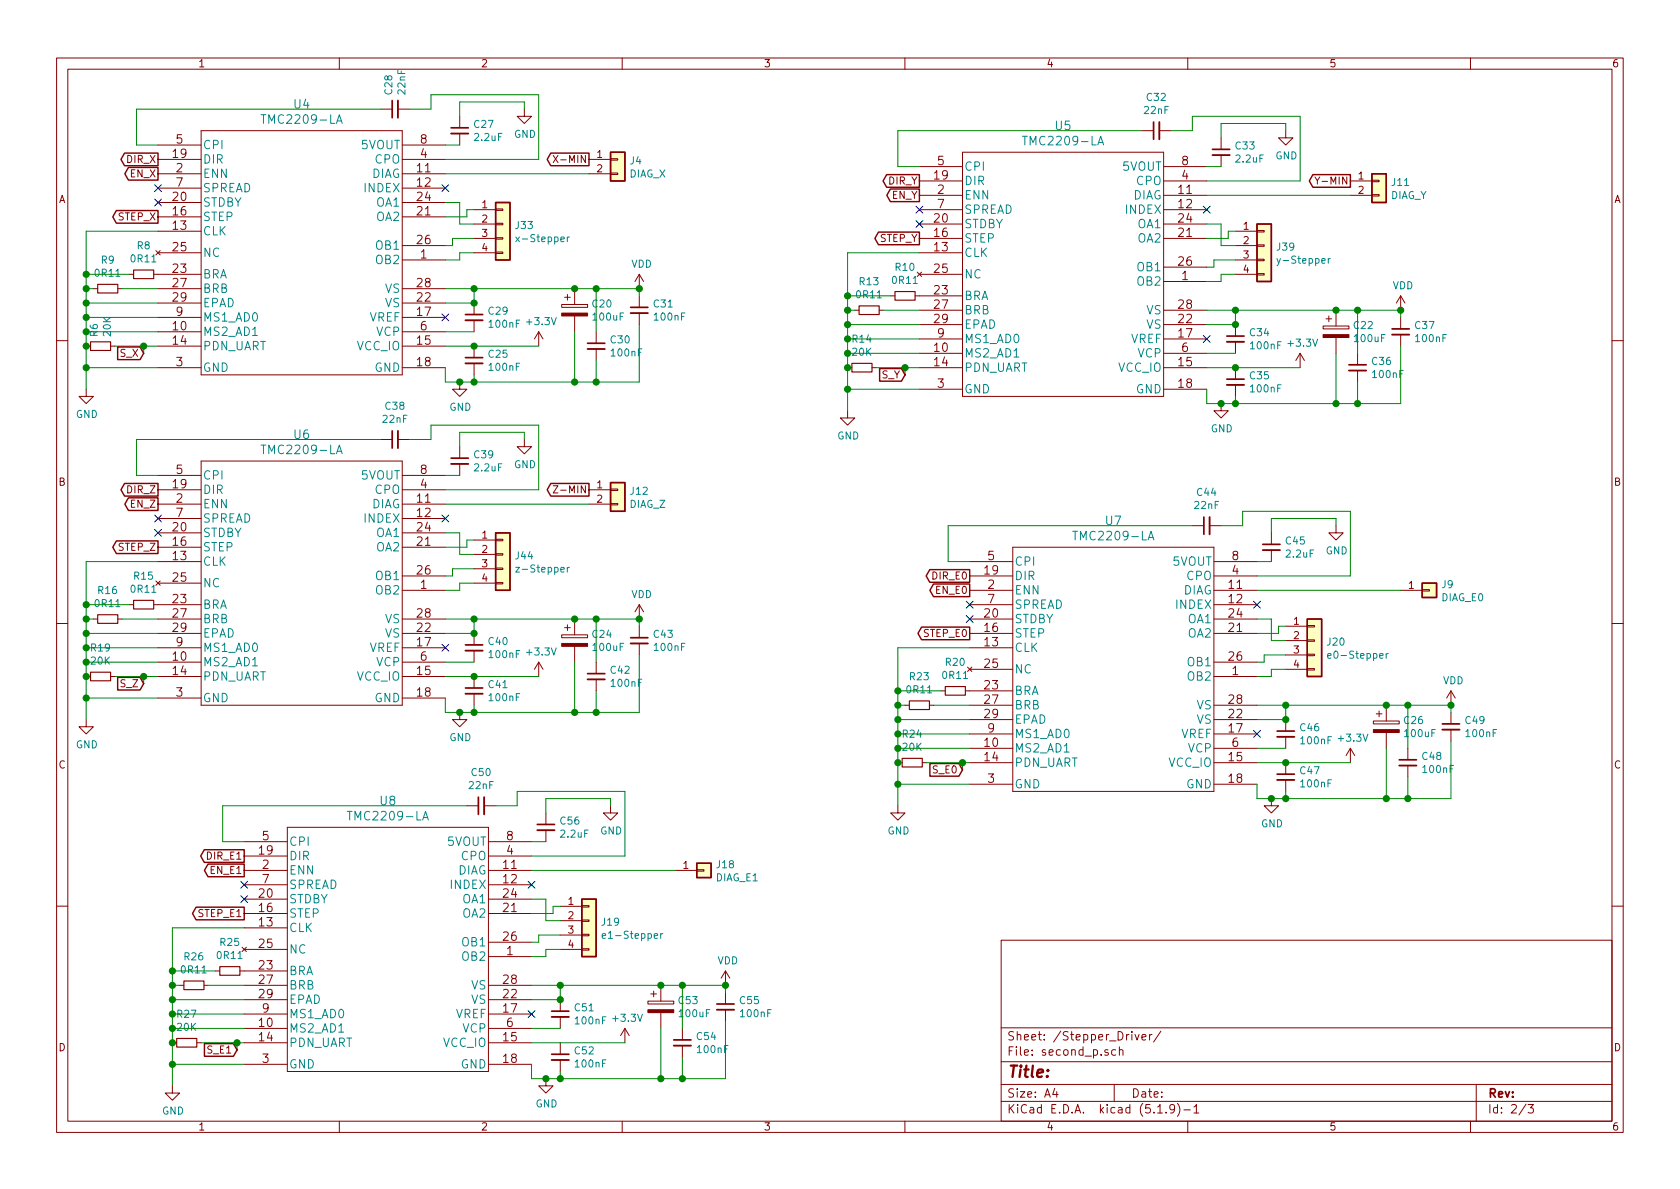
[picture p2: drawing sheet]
<svg xmlns="http://www.w3.org/2000/svg" width="297mm" height="210mm" viewBox="0 0 297 210" stroke-linecap="round" stroke-linejoin="round" font-family="sans-serif">
<defs><g id="words">
<text font-size="2.8" fill="#840000" x="178" y="190.5">Title:</text>
<g font-size="2.1" fill="#008484">
<text x="46.9" y="21.9">TMC2209-LA</text>
<text x="52" y="19.2">U4</text>
<text x="186.6" y="23">U5</text>
<text x="35.8" y="28.9">DIR</text>
<text x="35.8" y="26.4">CPI</text>
<text x="63.9" y="26.4">5VOUT</text>
<text x="66.3" y="28.9">CPO</text>
<text x="181.5" y="25.7">TMC2209-LA</text>
<text x="35.8" y="31.5">ENN</text>
<text x="35.8" y="34">SPREAD</text>
<text x="64.5" y="34">INDEX</text>
<text x="65.7" y="31.5">DIAG</text>
<text x="170.4" y="32.7">DIR</text>
<text x="170.4" y="35.3">ENN</text>
<text x="170.4" y="30.2">CPI</text>
<text x="198.5" y="30.2">5VOUT</text>
<text x="200.3" y="35.3">DIAG</text>
<text x="201" y="32.7">CPO</text>
<text x="35.8" y="41.6">CLK</text>
<text x="35.8" y="39.1">STEP</text>
<text x="35.8" y="36.5">STDBY</text>
<text x="66.6" y="39.1">OA2</text>
<text x="66.6" y="36.5">OA1</text>
<text x="170.4" y="40.4">STDBY</text>
<text x="170.4" y="37.8">SPREAD</text>
<text x="199.1" y="37.8">INDEX</text>
<text x="201.2" y="40.4">OA1</text>
<text x="35.8" y="45.4">NC</text>
<text x="66.6" y="46.7">OB2</text>
<text x="66.6" y="44.2">OB1</text>
<text x="170.4" y="45.4">CLK</text>
<text x="170.4" y="42.9">STEP</text>
<text x="201.2" y="42.9">OA2</text>
<text x="201.2" y="48">OB1</text>
<text x="35.8" y="49.2">BRA</text>
<text x="35.8" y="51.8">BRB</text>
<text x="68.1" y="51.8">VS</text>
<text x="170.4" y="53.1">BRA</text>
<text x="170.4" y="49.2">NC</text>
<text x="201.2" y="50.5">OB2</text>
<text x="35.8" y="59.4">MS2_AD1</text>
<text x="35.8" y="54.3">EPAD</text>
<text x="35.8" y="56.9">MS1_AD0</text>
<text x="65.3" y="56.9">VREF</text>
<text x="66.6" y="59.4">VCP</text>
<text x="68.1" y="54.3">VS</text>
<text x="170.4" y="55.6">BRB</text>
<text x="170.4" y="58.1">EPAD</text>
<text x="202.7" y="58.1">VS</text>
<text x="202.7" y="55.6">VS</text>
<text x="35.8" y="61.9">PDN_UART</text>
<text x="35.8" y="65.8">GND</text>
<text x="63.1" y="61.9">VCC_IO</text>
<text x="66.2" y="65.8">GND</text>
<text x="170.4" y="63.2">MS2_AD1</text>
<text x="170.4" y="65.8">PDN_UART</text>
<text x="170.4" y="60.7">MS1_AD0</text>
<text x="197.7" y="65.8">VCC_IO</text>
<text x="199.9" y="60.7">VREF</text>
<text x="201.2" y="63.2">VCP</text>
<text x="170.4" y="69.6">GND</text>
<text x="200.8" y="69.6">GND</text>
<text x="52" y="77.6">U6</text>
<text x="46.9" y="80.3">TMC2209-LA</text>
<text x="35.8" y="87.3">DIR</text>
<text x="35.8" y="89.9">ENN</text>
<text x="35.8" y="84.8">CPI</text>
<text x="63.9" y="84.8">5VOUT</text>
<text x="65.7" y="89.9">DIAG</text>
<text x="66.3" y="87.3">CPO</text>
<text x="35.8" y="95">STDBY</text>
<text x="35.8" y="92.4">SPREAD</text>
<text x="64.5" y="92.4">INDEX</text>
<text x="66.6" y="95">OA1</text>
<text x="190.4" y="95.5">TMC2209-LA</text>
<text x="195.5" y="92.9">U7</text>
<text x="35.8" y="100">CLK</text>
<text x="35.8" y="97.5">STEP</text>
<text x="66.6" y="97.5">OA2</text>
<text x="179.3" y="100">CPI</text>
<text x="207.4" y="100">5VOUT</text>
<text x="35.8" y="107.7">BRA</text>
<text x="35.8" y="103.9">NC</text>
<text x="66.6" y="105.1">OB2</text>
<text x="66.6" y="102.6">OB1</text>
<text x="179.3" y="102.6">DIR</text>
<text x="179.3" y="105.1">ENN</text>
<text x="179.3" y="107.7">SPREAD</text>
<text x="208" y="107.7">INDEX</text>
<text x="209.2" y="105.1">DIAG</text>
<text x="209.9" y="102.6">CPO</text>
<text x="35.8" y="110.2">BRB</text>
<text x="35.8" y="112.7">EPAD</text>
<text x="68.1" y="112.7">VS</text>
<text x="68.1" y="110.2">VS</text>
<text x="179.3" y="112.7">STEP</text>
<text x="179.3" y="110.2">STDBY</text>
<text x="210.1" y="112.7">OA2</text>
<text x="210.1" y="110.2">OA1</text>
<text x="35.8" y="117.8">MS2_AD1</text>
<text x="35.8" y="115.3">MS1_AD0</text>
<text x="65.3" y="115.3">VREF</text>
<text x="66.6" y="117.8">VCP</text>
<text x="179.3" y="115.3">CLK</text>
<text x="179.3" y="119.1">NC</text>
<text x="210.1" y="117.8">OB1</text>
<text x="35.8" y="120.4">PDN_UART</text>
<text x="35.8" y="124.2">GND</text>
<text x="63.1" y="120.4">VCC_IO</text>
<text x="66.2" y="124.2">GND</text>
<text x="179.3" y="122.9">BRA</text>
<text x="179.3" y="125.4">BRB</text>
<text x="210.1" y="120.4">OB2</text>
<text x="211.6" y="125.4">VS</text>
<text x="179.3" y="128">EPAD</text>
<text x="179.3" y="130.5">MS1_AD0</text>
<text x="208.8" y="130.5">VREF</text>
<text x="211.6" y="128">VS</text>
<text x="179.3" y="133.1">MS2_AD1</text>
<text x="179.3" y="135.6">PDN_UART</text>
<text x="206.6" y="135.6">VCC_IO</text>
<text x="210.1" y="133.1">VCP</text>
<text x="67.2" y="142.4">U8</text>
<text x="179.3" y="139.4">GND</text>
<text x="209.7" y="139.4">GND</text>
<text x="51.1" y="149.6">CPI</text>
<text x="62.2" y="145.1">TMC2209-LA</text>
<text x="79.1" y="149.6">5VOUT</text>
<text x="51.1" y="152.1">DIR</text>
<text x="51.1" y="154.7">ENN</text>
<text x="80.9" y="154.7">DIAG</text>
<text x="81.6" y="152.1">CPO</text>
<text x="51.1" y="159.7">STDBY</text>
<text x="51.1" y="157.2">SPREAD</text>
<text x="79.7" y="157.2">INDEX</text>
<text x="81.8" y="159.7">OA1</text>
<text x="51.1" y="164.8">CLK</text>
<text x="51.1" y="162.3">STEP</text>
<text x="81.8" y="162.3">OA2</text>
<text x="81.8" y="167.4">OB1</text>
<text x="51.1" y="172.4">BRA</text>
<text x="51.1" y="168.6">NC</text>
<text x="81.8" y="169.9">OB2</text>
<text x="51.1" y="175">BRB</text>
<text x="51.1" y="177.5">EPAD</text>
<text x="83.3" y="177.5">VS</text>
<text x="83.3" y="175">VS</text>
<text x="51.1" y="182.6">MS2_AD1</text>
<text x="51.1" y="185.1">PDN_UART</text>
<text x="51.1" y="180.1">MS1_AD0</text>
<text x="78.3" y="185.1">VCC_IO</text>
<text x="80.5" y="180.1">VREF</text>
<text x="81.8" y="182.6">VCP</text>
<text x="51.1" y="188.9">GND</text>
<text x="81.5" y="188.9">GND</text>
</g>
<g font-size="2.1" fill="#840000">
<text x="30.6" y="27.9">19</text>
<text x="31.2" y="25.4">5</text>
<text x="74.3" y="27.9">4</text>
<text x="74.3" y="25.4">8</text>
<text x="165.8" y="29.2">5</text>
<text x="209" y="29.2">8</text>
<text x="30.6" y="35.6">20</text>
<text x="31.2" y="30.5">2</text>
<text x="31.2" y="33">7</text>
<text x="73.8" y="30.5">11</text>
<text x="73.8" y="33">12</text>
<text x="73.8" y="35.6">24</text>
<text x="165.2" y="31.7">19</text>
<text x="165.8" y="34.3">2</text>
<text x="208.4" y="34.3">11</text>
<text x="209" y="31.7">4</text>
<text x="30.6" y="40.6">13</text>
<text x="30.6" y="38.1">16</text>
<text x="73.8" y="38.1">21</text>
<text x="165.2" y="41.9">16</text>
<text x="165.2" y="39.4">20</text>
<text x="165.8" y="36.8">7</text>
<text x="208.4" y="36.8">12</text>
<text x="208.4" y="41.9">21</text>
<text x="208.4" y="39.4">24</text>
<text x="30.6" y="44.4">25</text>
<text x="73.8" y="43.2">26</text>
<text x="74.3" y="45.7">1</text>
<text x="165.2" y="44.4">13</text>
<text x="208.4" y="47">26</text>
<text x="30.6" y="48.3">23</text>
<text x="30.6" y="50.8">27</text>
<text x="30.6" y="53.3">29</text>
<text x="73.8" y="53.3">22</text>
<text x="73.8" y="50.8">28</text>
<text x="165.2" y="52.1">23</text>
<text x="165.2" y="48.3">25</text>
<text x="209" y="49.5">1</text>
<text x="30.6" y="58.4">10</text>
<text x="31.2" y="55.9">9</text>
<text x="73.8" y="55.9">17</text>
<text x="74.3" y="58.4">6</text>
<text x="165.2" y="54.6">27</text>
<text x="165.2" y="57.1">29</text>
<text x="165.8" y="59.7">9</text>
<text x="208.4" y="59.7">17</text>
<text x="208.4" y="57.1">22</text>
<text x="208.4" y="54.6">28</text>
<text x="30.6" y="61">14</text>
<text x="31.2" y="64.8">3</text>
<text x="73.8" y="61">15</text>
<text x="73.8" y="64.8">18</text>
<text x="165.2" y="62.2">10</text>
<text x="165.2" y="64.8">14</text>
<text x="208.4" y="64.8">15</text>
<text x="209" y="62.2">6</text>
<text x="165.8" y="68.6">3</text>
<text x="208.4" y="68.6">18</text>
<text x="31.2" y="83.8">5</text>
<text x="74.3" y="83.8">8</text>
<text x="30.6" y="86.4">19</text>
<text x="31.2" y="88.9">2</text>
<text x="73.8" y="88.9">11</text>
<text x="74.3" y="86.4">4</text>
<text x="30.6" y="94">20</text>
<text x="31.2" y="91.4">7</text>
<text x="73.8" y="91.4">12</text>
<text x="73.8" y="94">24</text>
<text x="30.6" y="99.1">13</text>
<text x="30.6" y="96.5">16</text>
<text x="73.8" y="96.5">21</text>
<text x="73.8" y="101.6">26</text>
<text x="174.1" y="101.6">19</text>
<text x="174.7" y="99.1">5</text>
<text x="217.9" y="101.6">4</text>
<text x="217.9" y="99.1">8</text>
<text x="30.6" y="106.7">23</text>
<text x="30.6" y="102.9">25</text>
<text x="74.3" y="104.1">1</text>
<text x="174.7" y="104.1">2</text>
<text x="174.7" y="106.7">7</text>
<text x="217.3" y="104.1">11</text>
<text x="217.3" y="106.7">12</text>
<text x="30.6" y="109.2">27</text>
<text x="30.6" y="111.8">29</text>
<text x="73.8" y="111.8">22</text>
<text x="73.8" y="109.2">28</text>
<text x="174.1" y="111.8">16</text>
<text x="174.1" y="109.2">20</text>
<text x="217.3" y="111.8">21</text>
<text x="217.3" y="109.2">24</text>
<text x="30.6" y="116.8">10</text>
<text x="30.6" y="119.4">14</text>
<text x="31.2" y="114.3">9</text>
<text x="73.8" y="119.4">15</text>
<text x="73.8" y="114.3">17</text>
<text x="74.3" y="116.8">6</text>
<text x="174.1" y="114.3">13</text>
<text x="174.1" y="118.1">25</text>
<text x="217.3" y="116.8">26</text>
<text x="217.9" y="119.4">1</text>
<text x="31.2" y="123.2">3</text>
<text x="73.8" y="123.2">18</text>
<text x="174.1" y="121.9">23</text>
<text x="174.1" y="124.5">27</text>
<text x="217.3" y="124.5">28</text>
<text x="174.1" y="127">29</text>
<text x="174.7" y="129.5">9</text>
<text x="217.3" y="129.5">17</text>
<text x="217.3" y="127">22</text>
<text x="174.1" y="132.1">10</text>
<text x="174.1" y="134.6">14</text>
<text x="217.3" y="134.6">15</text>
<text x="217.9" y="132.1">6</text>
<text x="174.7" y="138.4">3</text>
<text x="217.3" y="138.4">18</text>
<text x="46.4" y="148.6">5</text>
<text x="89.6" y="148.6">8</text>
<text x="45.8" y="151.1">19</text>
<text x="46.4" y="153.7">2</text>
<text x="89" y="153.7">11</text>
<text x="89.6" y="151.1">4</text>
<text x="45.8" y="161.3">16</text>
<text x="45.8" y="158.7">20</text>
<text x="46.4" y="156.2">7</text>
<text x="89" y="156.2">12</text>
<text x="89" y="161.3">21</text>
<text x="89" y="158.7">24</text>
<text x="45.8" y="163.8">13</text>
<text x="45.8" y="167.6">25</text>
<text x="89" y="166.4">26</text>
<text x="45.8" y="171.4">23</text>
<text x="45.8" y="174">27</text>
<text x="89" y="174">28</text>
<text x="89.6" y="168.9">1</text>
<text x="45.8" y="176.5">29</text>
<text x="46.4" y="179.1">9</text>
<text x="89" y="179.1">17</text>
<text x="89" y="176.5">22</text>
<text x="45.8" y="181.6">10</text>
<text x="45.8" y="184.1">14</text>
<text x="89" y="184.1">15</text>
<text x="89.6" y="181.6">6</text>
<text x="178" y="184">Sheet: /Stepper_Driver/</text>
<text x="46.4" y="188">3</text>
<text x="89" y="188">18</text>
<text x="178" y="186.7">File: second_p.sch</text>
<text x="178" y="196.9">KiCad E.D.A. kicad (5.1.9)-1</text>
<text x="178" y="194.1">Size: A4</text>
<text x="200" y="194.1">Date:</text>
<text x="263" y="194.1">Rev:</text>
<text x="263" y="196.9">Id: 2/3</text>
</g>
<g font-size="1.8" fill="#840000">
<text x="35" y="11.9">1</text>
<text x="85" y="11.9">2</text>
<text x="135" y="11.9">3</text>
<text x="185" y="11.9">4</text>
<text x="235" y="11.9">5</text>
<text x="285" y="11.9">6</text>
<text x="22.5" y="28.8">DIR_X</text>
<text x="98.9" y="28.8">X-MIN</text>
<text x="105.6" y="27.9">1</text>
<text x="10.4" y="35.9">A</text>
<text x="23.1" y="31.4">EN_X</text>
<text x="105.6" y="30.5">2</text>
<text x="157.1" y="32.6">DIR_Y</text>
<text x="157.7" y="35.2">EN_Y</text>
<text x="233.5" y="32.6">Y-MIN</text>
<text x="240.2" y="31.7">1</text>
<text x="240.2" y="34.3">2</text>
<text x="285.4" y="35.9">A</text>
<text x="20.9" y="39">STEP_X</text>
<text x="85.2" y="36.8">1</text>
<text x="85.2" y="39.4">2</text>
<text x="85.2" y="41.9">3</text>
<text x="219.9" y="40.6">1</text>
<text x="85.2" y="44.4">4</text>
<text x="155.5" y="42.8">STEP_Y</text>
<text x="219.9" y="43.2">2</text>
<text x="219.9" y="45.7">3</text>
<text x="219.9" y="48.3">4</text>
<text x="21.3" y="63.1">S_X</text>
<text x="155.9" y="66.9">S_Y</text>
<text x="10.4" y="85.9">B</text>
<text x="22.6" y="87.2">DIR_Z</text>
<text x="23.2" y="89.8">EN_Z</text>
<text x="99" y="87.2">Z-MIN</text>
<text x="105.6" y="86.4">1</text>
<text x="105.6" y="88.9">2</text>
<text x="285.4" y="85.9">B</text>
<text x="85.2" y="95.2">1</text>
<text x="21" y="97.4">STEP_Z</text>
<text x="85.2" y="97.8">2</text>
<text x="85.2" y="100.3">3</text>
<text x="85.2" y="102.9">4</text>
<text x="165" y="102.5">DIR_E0</text>
<text x="165.6" y="105">EN_E0</text>
<text x="249.1" y="104.1">1</text>
<text x="163.4" y="112.6">STEP_E0</text>
<text x="228.8" y="110.5">1</text>
<text x="228.8" y="113">2</text>
<text x="228.8" y="115.6">3</text>
<text x="228.8" y="118.1">4</text>
<text x="21.4" y="121.5">S_Z</text>
<text x="10.4" y="135.9">C</text>
<text x="165.1" y="136.8">S_E0</text>
<text x="285.4" y="135.9">C</text>
<text x="36.7" y="152">DIR_E1</text>
<text x="37.3" y="154.6">EN_E1</text>
<text x="120.8" y="153.7">1</text>
<text x="100.5" y="160">1</text>
<text x="35.2" y="162.2">STEP_E1</text>
<text x="100.5" y="162.6">2</text>
<text x="100.5" y="165.1">3</text>
<text x="100.5" y="167.6">4</text>
<text x="10.4" y="185.9">D</text>
<text x="285.4" y="185.9">D</text>
<text x="36.8" y="186.3">S_E1</text>
<text x="35" y="199.9">1</text>
<text x="85" y="199.9">2</text>
<text x="135" y="199.9">3</text>
<text x="185" y="199.9">4</text>
<text x="235" y="199.9">5</text>
<text x="285" y="199.9">6</text>
</g>
<g font-size="1.8" fill="#008484">
<text x="69.4" y="16.7" transform="rotate(-90 69.4 16.7)">C28</text>
<text x="71.7" y="16.6" transform="rotate(-90 71.7 16.6)">22nF</text>
<text x="202.8" y="17.9">C32</text>
<text x="83.9" y="22.6">C27</text>
<text x="202.4" y="20.2">22nF</text>
<text x="84" y="24.9">2.2uF</text>
<text x="90.9" y="24.4">GND</text>
<text x="111.5" y="29.1">J4</text>
<text x="218.5" y="26.4">C33</text>
<text x="218.6" y="28.7">2.2uF</text>
<text x="225.5" y="28.2">GND</text>
<text x="111.3" y="31.4">DIAG_X</text>
<text x="245.8" y="35.2">DIAG_Y</text>
<text x="246.2" y="32.9">J11</text>
<text x="91.2" y="40.5">J33</text>
<text x="17.9" y="46.6">R9</text>
<text x="23.3" y="46.4">0R11</text>
<text x="24.3" y="44.1">R8</text>
<text x="91.8" y="42.8">x-Stepper</text>
<text x="111.6" y="47.3">VDD</text>
<text x="158.4" y="47.9">R10</text>
<text x="225.8" y="44.3">J39</text>
<text x="226.4" y="46.6">y-Stepper</text>
<text x="16.9" y="48.9">0R11</text>
<text x="151.5" y="52.8">0R11</text>
<text x="152" y="50.4">R13</text>
<text x="157.9" y="50.2">0R11</text>
<text x="246.2" y="51.1">VDD</text>
<text x="17.3" y="59.5" transform="rotate(-90 17.3 59.5)">R6</text>
<text x="19.6" y="59.4" transform="rotate(-90 19.6 59.4)">20K</text>
<text x="86.4" y="55.6">C29</text>
<text x="86.6" y="58">100nF</text>
<text x="93.3" y="57.5">+3.3V</text>
<text x="104.8" y="54.4">C20</text>
<text x="105" y="56.7">100uF</text>
<text x="115.6" y="54.4">C31</text>
<text x="115.8" y="56.7">100nF</text>
<text x="221.1" y="59.5">C34</text>
<text x="239.4" y="58.2">C22</text>
<text x="250.3" y="58.2">C37</text>
<text x="86.4" y="63.3">C25</text>
<text x="86.6" y="65.6">100nF</text>
<text x="108" y="60.7">C30</text>
<text x="108.2" y="63">100nF</text>
<text x="150.7" y="60.6">R14</text>
<text x="150.7" y="62.9">20K</text>
<text x="221.2" y="61.8">100nF</text>
<text x="227.9" y="61.3">+3.3V</text>
<text x="239.6" y="60.5">100uF</text>
<text x="242.6" y="64.5">C36</text>
<text x="250.4" y="60.5">100nF</text>
<text x="221.1" y="67.1">C35</text>
<text x="221.2" y="69.4">100nF</text>
<text x="242.8" y="66.8">100nF</text>
<text x="13.4" y="73.9">GND</text>
<text x="67.8" y="74.8">22nF</text>
<text x="68.2" y="72.5">C38</text>
<text x="79.5" y="72.6">GND</text>
<text x="148" y="77.7">GND</text>
<text x="214.1" y="76.4">GND</text>
<text x="83.9" y="81">C39</text>
<text x="84" y="83.4">2.2uF</text>
<text x="90.9" y="82.8">GND</text>
<text x="111.3" y="89.8">DIAG_Z</text>
<text x="111.5" y="87.5">J12</text>
<text x="211.7" y="87.7">C44</text>
<text x="211.3" y="90">22nF</text>
<text x="91.2" y="98.9">J44</text>
<text x="91.9" y="101.2">z-Stepper</text>
<text x="227.4" y="96.3">C45</text>
<text x="227.5" y="98.6">2.2uF</text>
<text x="234.4" y="98">GND</text>
<text x="16.9" y="107.4">0R11</text>
<text x="17.4" y="105">R16</text>
<text x="23.3" y="104.8">0R11</text>
<text x="23.7" y="102.5">R15</text>
<text x="111.6" y="105.8">VDD</text>
<text x="254.8" y="106.3">DIAG_E0</text>
<text x="255" y="104">J9</text>
<text x="104.8" y="112.8">C24</text>
<text x="115.6" y="112.8">C43</text>
<text x="16.1" y="115.2">R19</text>
<text x="16.1" y="117.5">20K</text>
<text x="86.4" y="114.1">C40</text>
<text x="86.6" y="116.4">100nF</text>
<text x="93.3" y="115.9">+3.3V</text>
<text x="105" y="115.1">100uF</text>
<text x="108" y="119.1">C42</text>
<text x="115.8" y="115.1">100nF</text>
<text x="167.3" y="117.7">R20</text>
<text x="234.7" y="114.2">J20</text>
<text x="235.5" y="116.5">e0-Stepper</text>
<text x="86.4" y="121.7">C41</text>
<text x="86.6" y="124">100nF</text>
<text x="108.2" y="121.5">100nF</text>
<text x="160.4" y="122.6">0R11</text>
<text x="160.9" y="120.3">R23</text>
<text x="166.8" y="120.1">0R11</text>
<text x="255.1" y="121">VDD</text>
<text x="79.5" y="131.1">GND</text>
<text x="159.6" y="130.4">R24</text>
<text x="229.9" y="129.3">C46</text>
<text x="230.1" y="131.6">100nF</text>
<text x="236.8" y="131.2">+3.3V</text>
<text x="248.3" y="128">C26</text>
<text x="248.5" y="130.3">100uF</text>
<text x="259.2" y="128">C49</text>
<text x="259.3" y="130.3">100nF</text>
<text x="13.4" y="132.3">GND</text>
<text x="83.4" y="137.2">C50</text>
<text x="159.6" y="132.8">20K</text>
<text x="229.9" y="136.9">C47</text>
<text x="251.5" y="134.4">C48</text>
<text x="251.7" y="136.7">100nF</text>
<text x="83" y="139.5">22nF</text>
<text x="230.1" y="139.2">100nF</text>
<text x="99.1" y="145.8">C56</text>
<text x="99.2" y="148.1">2.2uF</text>
<text x="106.1" y="147.6">GND</text>
<text x="156.9" y="147.6">GND</text>
<text x="223" y="146.3">GND</text>
<text x="126.6" y="155.8">DIAG_E1</text>
<text x="126.8" y="153.5">J18</text>
<text x="39" y="167.3">R25</text>
<text x="106.5" y="163.7">J19</text>
<text x="107.2" y="166">e1-Stepper</text>
<text x="32.2" y="172.1">0R11</text>
<text x="32.6" y="169.8">R26</text>
<text x="38.5" y="169.6">0R11</text>
<text x="126.8" y="170.5">VDD</text>
<text x="31.4" y="180">R27</text>
<text x="101.7" y="178.8">C51</text>
<text x="120" y="177.6">C53</text>
<text x="120.2" y="179.9">100uF</text>
<text x="130.9" y="177.6">C55</text>
<text x="131.1" y="179.9">100nF</text>
<text x="31.4" y="182.3">20K</text>
<text x="101.9" y="181.1">100nF</text>
<text x="108.5" y="180.7">+3.3V</text>
<text x="123.3" y="183.9">C54</text>
<text x="101.7" y="186.5">C52</text>
<text x="101.9" y="188.8">100nF</text>
<text x="123.4" y="186.2">100nF</text>
<text x="28.7" y="197.1">GND</text>
<text x="94.7" y="195.8">GND</text>
</g>
</g></defs>
<g fill="none" stroke="#840000" stroke-width=".18">
<path d="M10 10.3h277v189.9h-277zM12 12.2h273v186.1h-273zM60 10.3v1.9M67.3 19.3h2M70.4 19.3h2M92.7 19.3v1.3h1.3l-1.3 1.2-1.3-1.2h1.3M110 10.3v1.9M160 10.3v1.9M210 10.3v1.9M260 10.3v1.9M27.9 28.2h7.7M27.9 30.7h7.7"/>
<path d="M27.9 33.3h7.7M27.9 38.3h7.7M27.9 35.8h7.7M27.9 25.6h7.7M35.6 23.1h35.5v43.2h-35.5zM71.1 28.2h7.6M71.1 30.7h7.6M71.1 33.3h7.6M71.1 38.3h7.6M71.1 35.8h7.6M71.1 25.6h7.6M81.3 20.6v2"/>
<path d="M81.3 23.6v2M83.8 37.1h3.8M83.8 39.6h3.8M87.6 37h1.3v.2h-1.3zM87.6 39.5h1.3v.2h-1.3zM97.8 27.5l.9 1.2M98.7 27.5l-.9 1.2M104.1 28.2h3.8M104.1 30.7h3.8M107.9 30.6h1.3v.3h-1.3zM107.9 28.1h1.3v.2h-1.3zM162.6 32h7.6"/>
<path d="M162.6 34.5h7.6M162.6 37.1h7.6M162.6 39.6h7.6M162.6 29.5h7.6M170.2 26.9h35.5v43.2h-35.5zM201.9 23.1h2.1M205 23.1h2M205.7 32h7.7M205.7 34.5h7.7M205.7 37.1h7.7M205.7 39.6h7.7M205.7 29.5h7.7"/>
<path d="M215.9 24.4v2M215.9 27.4v2.1M227.3 23.1v1.3h1.3l-1.3 1.2-1.2-1.2h1.2M232.5 31.3l.4 .6 .4-.6M238.8 32h3.8M238.8 34.5h3.8M242.6 34.4h1.2v.3h-1.2zM242.6 31.9h1.2v.2h-1.2zM16.5 51h.8M20.8 51h.8M22.9 48.5h.7M27.2 48.5h8.4"/>
<path d="M27.6 44.3l.7 .8M27.9 51h7.7M27.9 44.7h7.7M27.9 58.7h7.7M27.9 40.9h7.7M27.9 56.1h7.7M27.9 53.6h7.7M28.3 44.3l-.7 .8M71.1 51h7.6M71.1 46h7.6M71.1 58.7h7.6M71.1 56.1h7.6"/>
<path d="M71.1 53.6h7.6M71.1 43.4h7.6M83.8 53.6v2M83.8 56.6v2.1M83.8 44.7h3.8M83.8 42.2h3.8M87.6 44.6h1.3v.2h-1.3zM87.6 42h1.3v.3h-1.3zM95.2 58.7v2.5M95.2 58.7l-.7 1.2M95.2 58.7l.8 1.2M99.3 53.8h4.6v.6h-4.6z"/>
<path d="M99.8 52.6h1M100.3 52.1v1M101.6 51v2.8M101.6 55.9v2.8M105.4 58.7v2M113 48.5v2.5M113 52.3v2.1M113 55.4v2M113 48.5l-.7 1.3M113 48.5l.8 1.3M151.1 54.9h.8M155.4 54.9h.8"/>
<path d="M157.5 52.3h.7M161.8 52.3h8.4M162.2 48.1l.7 .8M162.6 54.9h7.6M162.6 48.5h7.6M162.6 44.7h7.6M162.6 42.2h7.6M162.6 59.9h7.6M162.6 57.4h7.6M162.9 48.1l-.7 .8M205.7 54.9h7.7M205.7 49.8h7.7"/>
<path d="M205.7 42.2h7.7M205.7 59.9h7.7M205.7 57.4h7.7M205.7 47.2h7.7M218.4 48.5h3.8M218.4 57.4v2M218.4 46h3.8M218.4 40.9h3.8M218.4 43.4h3.8M222.2 48.4h1.3v.2h-1.3zM222.2 45.8h1.3v.3h-1.3zM222.2 40.8h1.3v.2h-1.3z"/>
<path d="M222.2 43.3h1.3v.3h-1.3zM233.9 57.7h4.6v.5h-4.6zM234.4 56.4h1.1M234.9 55.9v1M236.2 54.9v2.8M236.2 59.7v2.8M247.6 52.3v2.6M247.6 56.1v2.1M247.6 59.2v2M247.6 52.3l-.7 1.3M247.6 52.3l.8 1.3M10 60.2h2"/>
<path d="M15.2 68.8v1.3h1.3l-1.3 1.3-1.2-1.3h1.2M15.2 61.2h.8M19.6 61.2h.7M27.9 65h7.7M27.9 61.2h7.7M67.3 77.7h2M70.4 77.7h2M71.1 65h7.6M71.1 61.2h7.6M81.3 67.6v1.2h1.2l-1.2 1.3-1.3-1.3h1.3M81.3 79v2M83.8 61.2v2"/>
<path d="M83.8 64.3v2M92.7 77.7v1.3h1.3l-1.3 1.3-1.3-1.3h1.3M105.4 61.7v2M149.9 72.6v1.3h1.2l-1.2 1.3-1.3-1.3h1.3M149.9 65h.7M154.2 65h.7M162.6 65h7.6M162.6 62.5h7.6M162.6 68.8h7.6M205.7 65h7.7M205.7 62.5h7.7M205.7 68.8h7.7"/>
<path d="M215.9 71.4v1.2h1.3l-1.3 1.3-1.3-1.3h1.3M218.4 60.4v2.1M218.4 65v2.1M218.4 68.1v2M229.9 62.5l-.8 1.2M229.9 62.5v2.5M229.9 62.5l.7 1.2M240 62.5v2M240 65.5v2.1M285 60.2h2M27.9 89.1h7.7M27.9 91.7h7.7"/>
<path d="M27.9 99.3h7.7M27.9 96.8h7.7M27.9 86.6h7.7M27.9 94.2h7.7M27.9 84.1h7.7M35.6 81.5h35.5v43.2h-35.5zM71.1 89.1h7.6M71.1 91.7h7.6M71.1 96.8h7.6M71.1 86.6h7.6M71.1 94.2h7.6M71.1 84.1h7.6"/>
<path d="M81.3 82v2.1M83.8 95.5h3.8M83.8 98h3.8M87.6 95.4h1.3v.2h-1.3zM87.6 97.9h1.3v.3h-1.3zM97.8 85.9h.9l-.9 1.3h.9M104.1 89.1h3.8M104.1 86.6h3.8M107.9 89h1.3v.3h-1.3zM107.9 86.5h1.3v.2h-1.3zM171.4 99.3h7.7M179.1 96.8h35.5v43.1h-35.5z"/>
<path d="M210.8 93h2.1M213.9 93h2M214.6 99.3h7.6M224.8 94.2v2.1M224.8 97.3v2M236.2 93v1.2h1.3l-1.3 1.3-1.3-1.3h1.3M10 110.3h2M15.2 119.6h.8M16.5 109.5h.8M19.6 119.6h.7M20.8 109.5h.8M22.9 106.9h.7"/>
<path d="M27.2 106.9h8.4M27.6 102.7l.7 .8M27.9 117.1h7.7M27.9 119.6h7.7M27.9 114.5h7.7M27.9 112h7.7M27.9 103.1h7.7M27.9 109.5h7.7M28.3 102.7l-.7 .8M71.1 104.4h7.6M71.1 117.1h7.6M71.1 119.6h7.6"/>
<path d="M71.1 114.5h7.6M71.1 112h7.6M71.1 101.8h7.6M71.1 109.5h7.6M83.8 103.1h3.8M83.8 112v2M83.8 115.1v2M83.8 119.6v2.1M83.8 100.6h3.8M87.6 103h1.3v.2h-1.3zM87.6 100.5h1.3v.2h-1.3zM95.2 117.1l-.7 1.3"/>
<path d="M95.2 117.1v2.5M95.2 117.1l.8 1.3M99.3 112.3h4.6v.5h-4.6zM99.8 111h1M100.3 110.5v1M101.6 109.5v2.8M101.6 114.3v2.8M105.4 117.1v2M113 106.9l-.7 1.3M113 106.9v2.6M113 110.7v2.1M113 113.8v2"/>
<path d="M113 106.9l.8 1.3M171.1 118l.7 .7M171.4 104.4h7.7M171.4 114.5h7.7M171.4 112h7.7M171.4 106.9h7.7M171.4 101.8h7.7M171.4 109.5h7.7M171.4 118.4h7.7M171.8 118l-.7 .7M214.6 104.4h7.6M214.6 117.1h7.6"/>
<path d="M214.6 119.6h7.6M214.6 112h7.6M214.6 106.9h7.6M214.6 101.8h7.6M214.6 109.5h7.6M227.3 118.4h3.8M227.3 110.7h3.8M227.3 113.3h3.8M227.3 115.8h3.8M231.1 118.2h1.3v.3h-1.3zM231.1 115.7h1.3v.2h-1.3zM231.1 110.6h1.3v.3h-1.3z"/>
<path d="M231.1 113.2h1.3v.2h-1.3zM247.6 104.4h3.9M251.5 104.3h1.2v.2h-1.2zM285 110.3h2M15.2 127.2v1.3h1.3l-1.3 1.3-1.2-1.3h1.2M27.9 123.4h7.7M71.1 123.4h7.6M81.3 126v1.2h1.2l-1.2 1.3-1.3-1.3h1.3M83.8 122.7v2M105.4 120.1v2.1M158.7 134.9h.8M160 124.7h.8"/>
<path d="M163.1 134.9h.7M164.3 124.7h.8M166.4 122.2h.7M170.7 122.2h8.4M171.4 124.7h7.7M171.4 134.9h7.7M171.4 132.3h7.7M171.4 129.8h7.7M171.4 138.7h7.7M171.4 127.2h7.7M214.6 124.7h7.6M214.6 134.9h7.6"/>
<path d="M214.6 132.3h7.6M214.6 129.8h7.6M214.6 138.7h7.6M214.6 127.2h7.6M227.3 127.2v2.1M227.3 130.3v2M227.3 134.9v2M227.3 137.9v2M238.8 132.3l-.8 1.3M238.8 132.3v2.6M238.8 132.3l.7 1.3M242.8 127.5h4.6v.5h-4.6z"/>
<path d="M243.3 126.2h1M243.8 125.7v1M245.1 124.7v2.8M245.1 129.5v2.8M248.9 132.3v2.1M248.9 135.4v2M256.5 122.2l-.7 1.2M256.5 122.2v2.5M256.5 126v2M256.5 129v2.1M256.5 122.2l.8 1.2M43.2 153.9h7.6"/>
<path d="M43.2 156.5h7.6M43.2 151.4h7.6M43.2 159h7.6M43.2 148.8h7.6M50.8 146.3h35.6v43.2h-35.6zM82.5 142.5h2.1M85.6 142.5h2M86.4 153.9h7.6M86.4 156.5h7.6M86.4 151.4h7.6M86.4 159h7.6M86.4 148.8h7.6"/>
<path d="M96.5 143.8v2M96.5 146.8v2M107.9 142.5v1.3h1.3l-1.3 1.2-1.2-1.2h1.2M119.4 153.9h3.8M123.2 153.8h1.3v.2h-1.3zM158.7 142.5v1.3h1.3l-1.3 1.2-1.2-1.2h1.2M224.8 141.2v1.3h1.3l-1.3 1.3-1.3-1.3h1.3M10 160.2h2M31.7 174.2h.8M36.1 174.2h.7M38.1 171.7h.8M42.4 171.7h8.4"/>
<path d="M42.8 167.5l.8 .8M43.2 174.2h7.6M43.2 164.1h7.6M43.2 161.5h7.6M43.2 179.3h7.6M43.2 176.8h7.6M43.2 167.9h7.6M43.6 167.5l-.8 .8M86.4 174.2h7.6M86.4 169.2h7.6M86.4 161.5h7.6M86.4 179.3h7.6"/>
<path d="M86.4 176.8h7.6M86.4 166.6h7.6M99.1 176.8v2M99.1 179.8v2.1M99.1 167.9h3.8M99.1 160.3h3.8M99.1 162.8h3.8M99.1 165.3h3.8M102.9 167.8h1.2v.2h-1.2zM102.9 165.2h1.2v.3h-1.2zM102.9 160.1h1.2v.3h-1.2zM102.9 162.7h1.2v.2h-1.2z"/>
<path d="M114.6 177h4.5v.5h-4.5zM115.1 175.8h1M115.6 175.3v1M116.8 174.2v2.8M116.8 179.1v2.8M128.3 171.7v2.5M128.3 175.5v2M128.3 178.6v2M128.3 171.7l-.8 1.3M128.3 171.7l.7 1.3M177 166.3h108v32h-108zM285 160.2h2"/>
<path d="M30.5 192v1.3h1.2l-1.2 1.3-1.3-1.3h1.3M30.5 184.4h.7M34.8 184.4h.8M43.2 184.4h7.6M43.2 181.9h7.6M43.2 188.2h7.6M60 198.3v1.9M86.4 184.4h7.6M86.4 181.9h7.6M86.4 188.2h7.6M96.5 190.7v1.3h1.3l-1.3 1.3-1.3-1.3h1.3M99.1 184.4v2"/>
<path d="M99.1 187.4v2.1M110 198.3v1.9M110.5 181.9l-.8 1.2M110.5 181.9v2.5M110.5 181.9l.8 1.2M120.6 181.9v2M120.6 184.9v2M160 198.3v1.9M177 194.8h108M177 191.8h108M177 187.8h108M177 181.8h108"/>
<path d="M186.5 192.5l-.4 1h1M186.8 193v1M197 191.8v3M197.3 185.7l-.5-.1-.3 .3 .1 .6 .2 .1 .5-.1M197.9 185.7h.1a.37 .37 0 0 1 .6 .1v.8M197.9 185.1v1.5M200.7 182.9l.3 1 .4-1M201.9 183.4l.7-.1-.1-.3-.4-.1-.2 .2 .1 .7h.5M203.3 182.9v1M203.7 182.9l-.4 .3M204.7 196.8h.8M205.3 182.3l-1.3 2"/>
<path d="M206.2 196.7v.1M207.7 196l-.1 .1a.48 .48 0 0 1-.6 .1l-.2-.2 .2-.6a.48 .48 0 0 1 .6 .1 1.27 1.27 0 0 1-.2 1.2l-.4 .1M208.2 195.1a1.71 1.71 0 0 1 0 2.3M209.3 196.3h1.2M210 198.3v1.9M211.1 195.8l.4-.5v1.5M211.1 196.8h.9M260 198.3v1.9M261 191.8v6.5M269.8 195.2l-1.2 2M270.2 195.3h.9l-.5 .6 .4 .1v.7l-.2 .1-.6-.1"/>
</g>
<g fill="none" stroke="#840000" stroke-width=".2">
<path d="M17.3 50.3h3.5v1.5h-3.5zM23.6 47.7h3.6v1.6h-3.6zM151.9 54.1h3.5v1.5h-3.5zM158.2 51.6h3.6v1.5h-3.6zM16 60.4h3.6v1.6h-3.6zM150.6 64.3h3.6v1.5h-3.6zM16 118.9h3.6v1.5h-3.6zM17.3 108.7h3.5v1.5h-3.5zM23.6 106.2h3.6v1.5h-3.6zM159.5 134.1h3.6v1.5h-3.6zM160.8 123.9h3.5v1.6h-3.5zM167.1 121.4h3.6v1.5h-3.6z"/>
<path d="M32.5 173.5h3.6v1.5h-3.6zM38.9 170.9h3.5v1.6h-3.5zM31.2 183.6h3.6v1.6h-3.6z"/>
</g>
<g fill="none" stroke="#840000" stroke-width=".33">
<path d="M70.4 17.8v3M79.8 23.6h3M205 21.6v3M214.4 27.4h3M82.3 56.6h3M111.5 55.4h3.1M246.1 59.2h3.1M70.4 76.2v3M82.3 64.3h3M103.9 61.7h3M216.9 68.1h3.1M216.9 60.4h3.1"/>
<path d="M238.5 65.5h3.1M79.8 82h3M213.9 91.4v3.1M223.3 97.3h3M82.3 115.1h3M111.5 113.8h3.1M82.3 122.7h3M103.9 120.1h3M225.8 137.9h3.1M225.8 130.3h3.1M247.4 135.4h3M255 129h3.1"/>
<path d="M85.6 141v3M95 146.8h3M97.5 179.8h3.1M126.7 178.6h3.1M97.5 187.4h3.1M119.1 184.9h3.1"/>
</g>
<g fill="none" stroke="#840000" stroke-width=".3">
<path d="M69.3 17.8v3M79.8 22.6h3M204 21.6v3M214.4 26.4h3M82.3 55.6h3M111.5 54.4h3.1M216.9 59.4h3.1M246.1 58.2h3.1M69.3 76.2v3M82.3 63.2h3M103.9 60.7h3M216.9 67.1h3.1"/>
<path d="M238.5 64.5h3.1M79.8 81h3M212.9 91.4v3.1M223.3 96.3h3M82.3 114h3M103.9 119.1h3M111.5 112.8h3.1M82.3 121.7h3M225.8 136.9h3.1M225.8 129.3h3.1M247.4 134.4h3M255 128h3.1"/>
<path d="M84.6 141v3M95 145.8h3M97.5 178.8h3.1M126.7 177.5h3.1M97.5 186.4h3.1M119.1 183.9h3.1"/>
</g>
<g fill="#ffffc2" stroke="#ffffc2" stroke-width=".18">
<path d="M123.2 152.6h2.5v2.6h-2.5z"/>
<path d="M242.6 30.7h2.5v5.1h-2.5z"/>
<path d="M107.9 26.9h2.6v5.1h-2.6z"/>
<path d="M107.9 85.3h2.6v5.1h-2.6z"/>
<path d="M87.6 35.8h2.6v10.2h-2.6z"/>
<path d="M102.9 159h2.5v10.2h-2.5z"/>
<path d="M251.5 103.1h2.5v2.6h-2.5z"/>
<path d="M231.1 109.5h2.6v10.1h-2.6z"/>
<path d="M87.6 94.2h2.6v10.2h-2.6z"/>
<path d="M222.2 39.6h2.6v10.2h-2.6z"/>
</g>
<g fill="none" stroke="#840000" stroke-width=".25">
<path d="M20.6 37.2h7.3v2.3h-7.3l-.7-1.2zM22 27.1h5.9v2.2h-5.9l-.6-1.1zM22.7 29.6h5.2v2.2h-5.2l-.6-1.1zM87.6 35.8h2.6v10.2h-2.6zM97.4 27.1h6.7v2.2h-6.7l-.7-1.1zM107.9 26.9h2.6v5.1h-2.6zM156.8 30.9h5.8v2.2h-5.8l-.7-1.1zM157.4 33.4h5.2v2.3h-5.2l-.6-1.2zM222.2 39.6h2.6v10.2h-2.6zM232.1 30.9h6.7v2.2h-6.7l-.6-1.1zM242.6 30.7h2.5v5.1h-2.5zM155.3 41h7.3v2.3h-7.3l-.6-1.1z"/>
<path d="M20.8 61.4h4l.6 1.1-.6 1.1h-4zM155.5 65.2h3.9l.6 1.1-.6 1.1h-3.9zM20.6 95.7h7.3v2.2h-7.3l-.7-1.1zM22 85.5h5.9v2.2h-5.9l-.6-1.1zM22.7 88h5.2v2.3h-5.2l-.6-1.2zM87.6 94.2h2.6v10.2h-2.6zM97.4 85.5h6.7v2.2h-6.7l-.7-1.1zM107.9 85.3h2.6v5.1h-2.6zM20.8 119.8h4l.6 1.1-.6 1.1h-4zM162.9 110.9h8.5v2.2h-8.5l-.6-1.1zM164.4 100.7h7v2.3h-7l-.6-1.2zM165 103.3h6.4v2.2h-6.4l-.6-1.1z"/>
<path d="M231.1 109.5h2.6v10.1h-2.6zM251.5 103.1h2.5v2.6h-2.5zM164.4 135h5.1l.7 1.1-.7 1.2h-5.1zM36.1 150.3h7.1v2.2h-7.1l-.6-1.1zM36.8 152.8h6.4v2.2h-6.4l-.7-1.1zM102.9 159h2.5v10.2h-2.5zM123.2 152.6h2.5v2.6h-2.5zM34.7 160.4h8.5v2.3h-8.5l-.7-1.2zM36.1 184.6h5.2l.6 1.1-.6 1.1h-5.2z"/>
</g>
<g fill="none" stroke="#008484" stroke-width=".18">
<path d="M46.2 20.3h.8M59.5 21.8l.5-1.5 .5 1.5M59.6 21.4h.8M180.8 24.1h.8M194.1 25.6l.5-1.5 .5 1.5M194.3 25.2h.7M91.2 41.9l.6 .8M91.8 41.9l-.6 .8M100.3 41.9v.8M100.7 41.9l-.4 .2M225.8 45.7l.3 .9M226.4 45.7l-.4 1.2-.2 .1"/>
<path d="M234.8 45.7v.9M235.2 45.7l-.4 .2M46.2 78.7h.8M59.6 79.8h.8M59.5 80.2l.5-1.5 .5 1.5M189.7 93.9h.8M203 95.5l.5-1.6 .5 1.6M203.1 95h.8M91.2 100.3h.6l-.6 .9h.6M100.3 100.3v.9M100.7 100.3l-.4 .3M234.7 116l.7-.1-.1-.3h-.4l-.2 .1 .1 .7h.5"/>
<path d="M245.1 115.6v.8M245.5 115.6l-.4 .2M61.4 143.5h.9M74.7 145l.5-1.5 .5 1.5M74.9 144.6h.7M106.5 165.5l.6-.1-.1-.3h-.3l-.2 .2 .1 .6h.4M116.8 165.1v.8M117.2 165.1l-.4 .2"/>
</g>
<g fill="#840000" stroke="#840000" stroke-width=".18">
<path d="M99.3 55.4h4.6v.5h-4.6z"/>
<path d="M114.6 178.6h4.5v.5h-4.5z"/>
<path d="M242.8 129h4.6v.5h-4.6z"/>
<path d="M99.3 113.8h4.6v.5h-4.6z"/>
<path d="M233.9 59.2h4.6v.5h-4.6z"/>
</g>
<g fill="none" stroke="#008400" stroke-width=".18">
<path d="M67.3 19.3h-43.2v6.3h3.8M72.4 19.3h3.8v-2.5h19v11.4h-16.5M92.7 19.3v-1.3h-11.4v2.6M78.7 35.8h2.6v3.8h2.5M78.7 30.7h25.4M78.7 25.6h2.6M83.8 37.1h-1.3v1.2h-3.8M201.9 23.1h-43.2v6.4h3.9M207 23.1h3.8v-2.5h19.1v11.4h-16.5M213.4 39.6h2.5v3.8h2.5M213.4 34.5h25.4M213.4 29.5h2.5"/>
<path d="M227.3 23.1v-1.3h-11.4v2.6M15.2 51h1.3M15.2 53.6h12.7M15.2 58.7h12.7M15.2 48.5h7.7M15.2 56.1h12.7M21.6 51h6.3M27.9 40.9h-12.7v27.9M78.7 51h34.3v1.3M78.7 58.7h5.1M83.8 44.7h-2.5v1.3h-2.6M83.8 42.2h-3.8v1.2h-1.3"/>
<path d="M83.8 51v2.6h-5.1M101.6 58.7v8.9M105.4 51v7.7M113 57.4v10.2h-34.3v-2.6M149.9 54.9h1.2M149.9 57.4h12.7M149.9 59.9h12.7M149.9 52.3h7.6M156.2 54.9h6.4M162.6 44.7h-12.7v27.9M213.4 54.9h34.2v1.2M218.4 40.9h-1.2v1.3h-3.8"/>
<path d="M218.4 48.5h-2.5v1.3h-2.5M218.4 54.9v2.5h-5M218.4 46h-3.8v1.2h-1.2M240 54.9v7.6M15.2 65h12.7M20.3 61.2h7.6M25.4 61.2v1.3M67.3 77.7h-43.2v6.4h3.8M72.4 77.7h3.8v-2.5h19v11.4h-16.5M78.7 61.2h16.5M83.8 66.3v1.3M92.7 77.7v-1.3h-11.4v2.6"/>
<path d="M105.4 63.7v3.9M149.9 62.5h12.7M149.9 68.8h12.7M154.9 65h7.7M160 65v1.3M213.4 65h16.5M213.4 62.5h5M218.4 70.1v1.3M236.2 62.5v8.9M240 67.6v3.8M247.6 61.2v10.2h-34.2v-2.6M27.9 99.3h-12.7v27.9"/>
<path d="M78.7 94.2h2.6v3.8h2.5M78.7 84.1h2.6M78.7 89.1h25.4M83.8 95.5h-1.3v1.3h-3.8M210.8 93h-43.2v6.3h3.8M215.9 93h3.8v-2.6h19.1v11.4h-16.6M222.2 99.3h2.6M236.2 93v-1.3h-11.4v2.5M15.2 109.5h1.3M15.2 117.1h12.7M15.2 112h12.7M15.2 106.9h7.7"/>
<path d="M15.2 114.5h12.7M20.3 119.6h7.6M21.6 109.5h6.3M25.4 119.6v1.3M78.7 119.6h16.5M78.7 109.5h34.3v1.2M78.7 117.1h5.1M83.8 103.1h-2.5v1.3h-2.6M83.8 109.5v2.5h-5.1M83.8 100.6h-3.8v1.2h-1.3M101.6 117.1v8.9M105.4 109.5v7.6"/>
<path d="M113 115.8v10.2h-34.3v-2.6M171.4 114.5h-12.7v28M222.2 109.5h2.6v3.8h2.5M222.2 104.4h25.4M227.3 118.4h-2.5v1.2h-2.6M227.3 115.8h-3.8v1.3h-1.3M227.3 110.7h-1.2v1.3h-3.9M15.2 123.4h12.7M83.8 124.7v1.3M105.4 122.2v3.8M158.7 124.7h1.3M158.7 129.8h12.7"/>
<path d="M158.7 127.2h12.7M158.7 132.3h12.7M158.7 122.2h7.7M158.7 138.7h12.7M163.8 134.9h7.6M165.1 124.7h6.3M170.2 134.9v1.2M222.2 134.9h16.6M222.2 124.7h34.3v1.3M222.2 132.3h5.1M227.3 124.7v2.5h-5.1M227.3 139.9v1.3"/>
<path d="M245.1 132.3v8.9M248.9 124.7v7.6M248.9 137.4v3.8M256.5 131.1v10.1h-34.3v-2.5M82.5 142.5h-43.1v6.3h3.8M87.6 142.5h3.8v-2.6h19.1v11.5h-16.5M94 159h2.5v3.8h2.6M94 148.8h2.5M94 153.9h25.4M107.9 142.5v-1.3h-11.4v2.6M30.5 176.8h12.7M30.5 174.2h1.2"/>
<path d="M30.5 179.3h12.7M30.5 171.7h7.6M36.8 174.2h6.4M43.2 164.1h-12.7v27.9M94 174.2h34.3v1.3M99.1 174.2v2.6h-5.1M99.1 167.9h-2.6v1.3h-2.5M99.1 160.3h-1.3v1.2h-3.8M99.1 165.3h-3.9v1.3h-1.2M120.6 174.2v7.7M30.5 181.9h12.7M30.5 188.2h12.7"/>
<path d="M35.6 184.4h7.6M41.9 184.4v1.3M94 184.4h16.5M94 181.9h5.1M99.1 189.5v1.2M116.8 181.9v8.8M120.6 186.9v3.8M128.3 180.6v10.1h-34.3v-2.5"/>
</g>
<g fill="#008400" stroke="#008400" stroke-width=".25">
<circle cx="149.9" cy="65" r=".51"/>
<circle cx="245.1" cy="124.7" r=".51"/>
<circle cx="218.4" cy="54.9" r=".51"/>
<circle cx="15.2" cy="53.6" r=".51"/>
<circle cx="170.2" cy="134.9" r=".51"/>
<circle cx="218.4" cy="65" r=".51"/>
<circle cx="83.8" cy="51" r=".51"/>
<circle cx="30.5" cy="184.4" r=".51"/>
<circle cx="227.3" cy="141.2" r=".51"/>
<circle cx="247.7" cy="54.9" r=".51"/>
<circle cx="227.3" cy="124.7" r=".51"/>
<circle cx="101.6" cy="67.6" r=".51"/>
<circle cx="25.4" cy="61.2" r=".51"/>
<circle cx="218.4" cy="71.4" r=".51"/>
<circle cx="105.4" cy="67.6" r=".51"/>
<circle cx="256.5" cy="124.7" r=".51"/>
<circle cx="128.3" cy="174.2" r=".51"/>
<circle cx="15.2" cy="61.2" r=".51"/>
<circle cx="25.4" cy="119.6" r=".51"/>
<circle cx="236.2" cy="54.9" r=".51"/>
<circle cx="83.8" cy="61.2" r=".51"/>
<circle cx="101.6" cy="51" r=".51"/>
<circle cx="99.1" cy="190.7" r=".51"/>
<circle cx="227.3" cy="134.9" r=".51"/>
<circle cx="41.9" cy="184.4" r=".51"/>
<circle cx="83.8" cy="119.6" r=".51"/>
<circle cx="83.8" cy="126" r=".51"/>
<circle cx="113" cy="109.5" r=".51"/>
<circle cx="15.2" cy="119.6" r=".51"/>
<circle cx="99.1" cy="174.2" r=".51"/>
<circle cx="81.3" cy="67.6" r=".51"/>
<circle cx="158.8" cy="134.9" r=".51"/>
<circle cx="105.4" cy="51" r=".51"/>
<circle cx="160" cy="65" r=".51"/>
<circle cx="83.8" cy="67.6" r=".51"/>
<circle cx="113" cy="51" r=".51"/>
<circle cx="83.8" cy="53.6" r=".51"/>
<circle cx="83.8" cy="109.5" r=".51"/>
<circle cx="158.8" cy="122.2" r=".51"/>
<circle cx="30.5" cy="179.3" r=".51"/>
<circle cx="120.6" cy="190.7" r=".51"/>
<circle cx="15.2" cy="56.1" r=".51"/>
<circle cx="120.7" cy="174.2" r=".51"/>
<circle cx="81.3" cy="126" r=".51"/>
<circle cx="99.1" cy="176.8" r=".51"/>
<circle cx="15.2" cy="112" r=".51"/>
<circle cx="83.8" cy="112" r=".51"/>
<circle cx="30.5" cy="176.8" r=".51"/>
<circle cx="96.5" cy="190.7" r=".51"/>
<circle cx="105.4" cy="109.5" r=".51"/>
<circle cx="101.6" cy="126" r=".51"/>
<circle cx="105.4" cy="126" r=".51"/>
<circle cx="15.2" cy="114.5" r=".51"/>
<circle cx="116.8" cy="190.7" r=".51"/>
<circle cx="15.2" cy="117.1" r=".51"/>
<circle cx="158.8" cy="124.7" r=".51"/>
<circle cx="15.2" cy="109.5" r=".51"/>
<circle cx="158.8" cy="132.3" r=".51"/>
<circle cx="15.2" cy="106.9" r=".51"/>
<circle cx="101.6" cy="109.5" r=".51"/>
<circle cx="158.8" cy="129.8" r=".51"/>
<circle cx="248.9" cy="141.2" r=".51"/>
<circle cx="245.1" cy="141.2" r=".51"/>
<circle cx="248.9" cy="124.7" r=".51"/>
<circle cx="224.8" cy="141.2" r=".51"/>
<circle cx="227.3" cy="127.2" r=".51"/>
<circle cx="158.8" cy="127.2" r=".51"/>
<circle cx="30.5" cy="188.2" r=".51"/>
<circle cx="15.2" cy="51" r=".51"/>
<circle cx="15.2" cy="48.5" r=".51"/>
<circle cx="15.2" cy="65" r=".51"/>
<circle cx="215.9" cy="71.4" r=".51"/>
<circle cx="149.9" cy="68.8" r=".51"/>
<circle cx="149.9" cy="57.4" r=".51"/>
<circle cx="149.9" cy="52.3" r=".51"/>
<circle cx="15.2" cy="58.7" r=".51"/>
<circle cx="218.4" cy="57.4" r=".51"/>
<circle cx="240" cy="54.9" r=".51"/>
<circle cx="236.2" cy="71.4" r=".51"/>
<circle cx="240" cy="71.4" r=".51"/>
<circle cx="149.9" cy="59.9" r=".51"/>
<circle cx="116.8" cy="174.2" r=".51"/>
<circle cx="30.5" cy="171.7" r=".51"/>
<circle cx="30.5" cy="174.2" r=".51"/>
<circle cx="15.2" cy="123.4" r=".51"/>
<circle cx="149.9" cy="62.5" r=".51"/>
<circle cx="149.9" cy="54.9" r=".51"/>
<circle cx="30.5" cy="181.9" r=".51"/>
<circle cx="158.8" cy="138.7" r=".51"/>
</g>
<g fill="none" stroke="#000084" stroke-width=".18">
<path d="M27.3 35.2l1.2 1.2M27.3 32.7l1.2 1.2M28.5 35.2l-1.2 1.2M28.5 32.7l-1.2 1.2M78.1 32.7l1.2 1.2M79.3 32.7l-1.2 1.2M162 36.5l1.2 1.2M162 39l1.2 1.2M163.2 36.5l-1.2 1.2M163.2 39l-1.2 1.2M212.8 36.5l1.2 1.2M214 36.5l-1.2 1.2"/>
<path d="M78.1 55.5l1.2 1.2M79.3 55.5l-1.2 1.2M212.8 59.3l1.2 1.2M214 59.3l-1.2 1.2M27.3 93.6l1.2 1.2M27.3 91.1l1.2 1.2M28.5 93.6l-1.2 1.2M28.5 91.1l-1.2 1.2M78.1 91.1l1.2 1.2M79.3 91.1l-1.2 1.2M78.1 113.9l1.2 1.3M79.3 113.9l-1.2 1.3"/>
<path d="M170.8 106.3l1.3 1.2M170.8 108.9l1.3 1.2M172.1 106.3l-1.3 1.2M172.1 108.9l-1.3 1.2M221.6 106.3l1.3 1.2M222.9 106.3l-1.3 1.2M221.6 129.2l1.3 1.2M222.9 129.2l-1.3 1.2M42.6 155.8l1.2 1.3M42.6 158.4l1.2 1.2M43.8 155.8l-1.2 1.3M43.8 158.4l-1.2 1.2"/>
<path d="M93.4 155.8l1.2 1.3M94.6 155.8l-1.2 1.3M93.4 178.7l1.2 1.2M94.6 178.7l-1.2 1.2"/>
</g>
<use href="#words"/>
</svg>
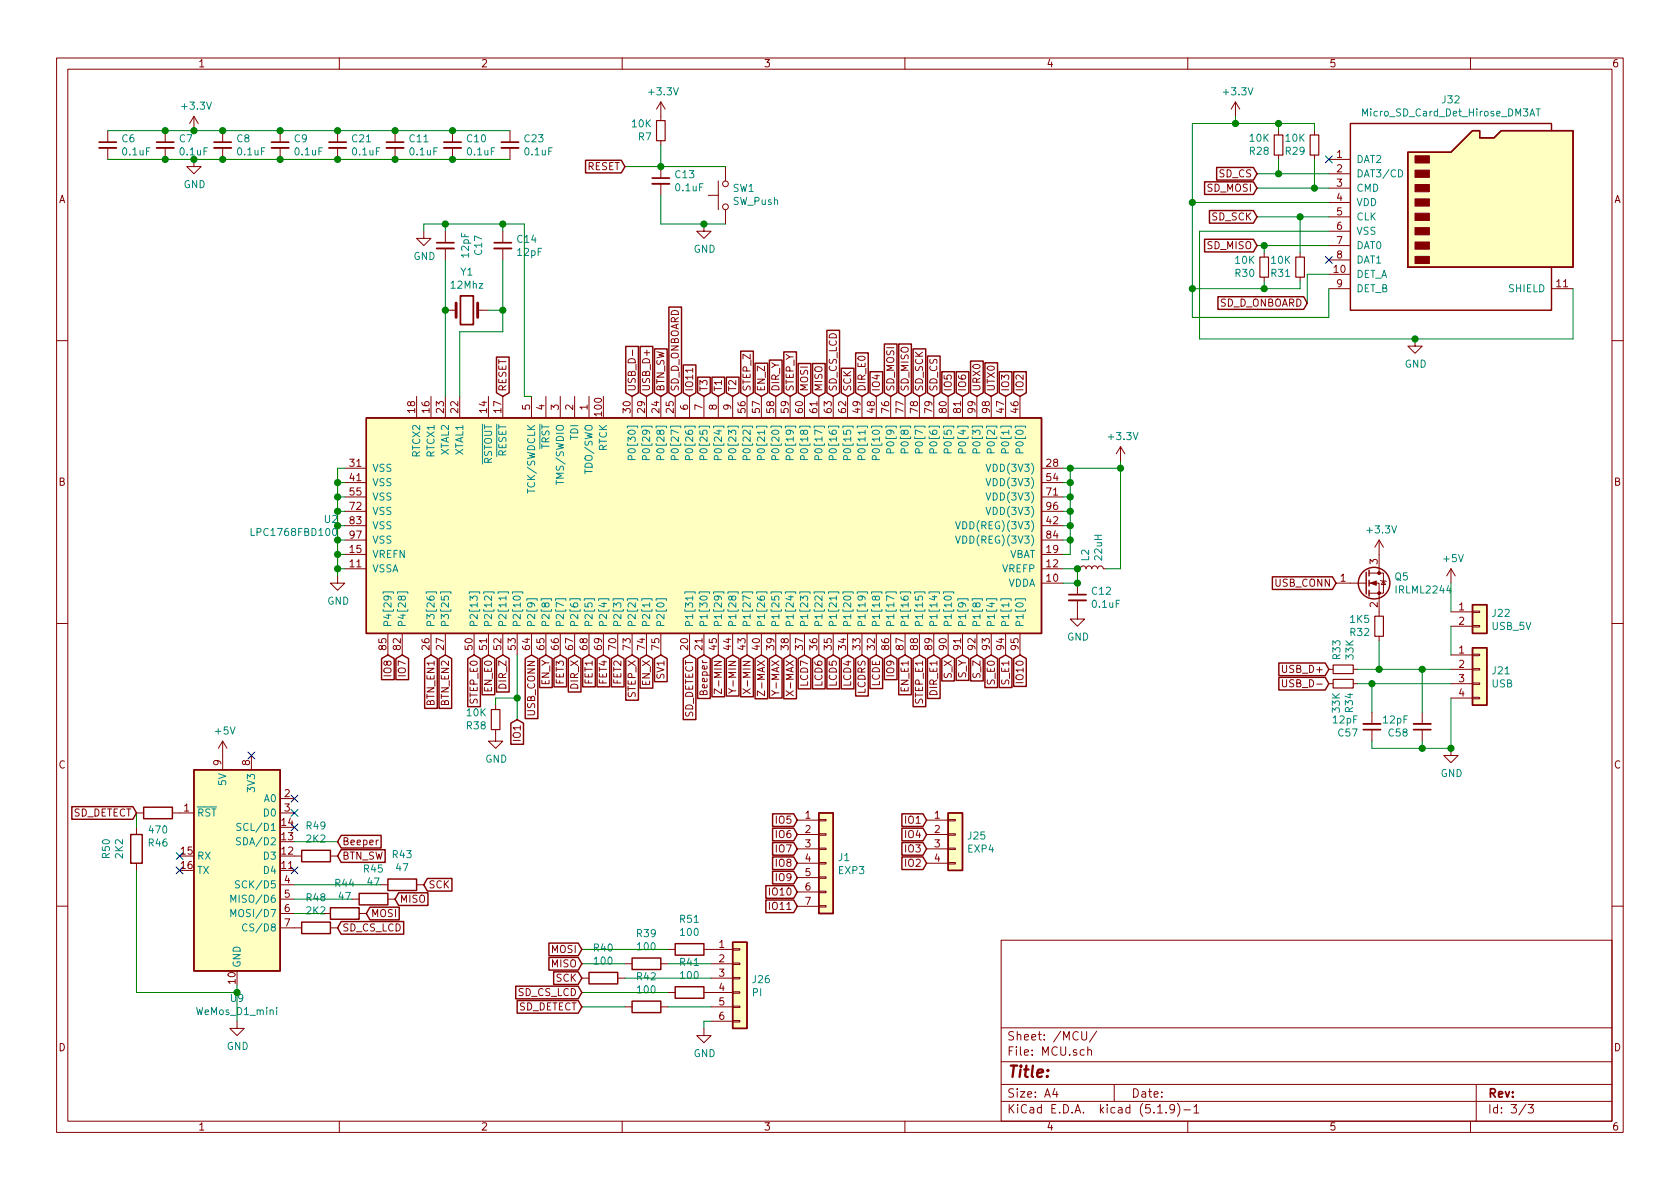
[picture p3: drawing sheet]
<svg xmlns="http://www.w3.org/2000/svg" width="297mm" height="210mm" viewBox="0 0 297 210" stroke-linecap="round" stroke-linejoin="round" font-family="sans-serif">
<defs><g id="words">
<text font-size="2.8" fill="#840000" x="178" y="190.5">Title:</text>
<g font-size="2.1" fill="#840000">
<text x="178" y="184">Sheet: /MCU/</text>
<text x="178" y="186.7">File: MCU.sch</text>
<text x="178" y="196.9">KiCad E.D.A. kicad (5.1.9)-1</text>
<text x="178" y="194.1">Size: A4</text>
<text x="200" y="194.1">Date:</text>
<text x="263" y="194.1">Rev:</text>
<text x="263" y="196.9">Id: 3/3</text>
</g>
<g font-size="1.8" fill="#840000">
<text x="35" y="11.9">1</text>
<text x="85" y="11.9">2</text>
<text x="135" y="11.9">3</text>
<text x="185" y="11.9">4</text>
<text x="235" y="11.9">5</text>
<text x="285" y="11.9">6</text>
<text x="236.4" y="27.9">1</text>
<text x="10.4" y="35.9">A</text>
<text x="103.8" y="30.1">RESET</text>
<text x="213.5" y="33.9">SD_MOSI</text>
<text x="215.6" y="31.4">SD_CS</text>
<text x="236.4" y="30.5">2</text>
<text x="236.4" y="33">3</text>
<text x="236.4" y="35.6">4</text>
<text x="285.4" y="35.9">A</text>
<text x="214.3" y="39">SD_SCK</text>
<text x="236.4" y="38.1">5</text>
<text x="236.4" y="40.6">6</text>
<text x="213.5" y="44.1">SD_MISO</text>
<text x="236.4" y="43.2">7</text>
<text x="236.4" y="45.7">8</text>
<text x="235.9" y="48.3">10</text>
<text x="236.4" y="50.8">9</text>
<text x="275.3" y="50.8">11</text>
<text x="215.5" y="54.2">SD_D_ONBOARD</text>
<text x="89.5" y="69.3" transform="rotate(-90 89.5 69.3)">RESET</text>
<text x="112.4" y="69.3" transform="rotate(-90 112.4 69.3)">USB_D-</text>
<text x="114.9" y="69.3" transform="rotate(-90 114.9 69.3)">USB_D+</text>
<text x="117.5" y="69.3" transform="rotate(-90 117.5 69.3)">BTN_SW</text>
<text x="120" y="69.3" transform="rotate(-90 120 69.3)">SD_D_ONBOARD</text>
<text x="122.6" y="69.3" transform="rotate(-90 122.6 69.3)">IO11</text>
<text x="125.1" y="69.3" transform="rotate(-90 125.1 69.3)">T3</text>
<text x="127.6" y="69.3" transform="rotate(-90 127.6 69.3)">T1</text>
<text x="130.2" y="69.3" transform="rotate(-90 130.2 69.3)">T2</text>
<text x="132.7" y="69.3" transform="rotate(-90 132.7 69.3)">STEP_Z</text>
<text x="135.3" y="69.3" transform="rotate(-90 135.3 69.3)">EN_Z</text>
<text x="137.8" y="69.3" transform="rotate(-90 137.8 69.3)">DIR_Y</text>
<text x="140.3" y="69.3" transform="rotate(-90 140.3 69.3)">STEP_Y</text>
<text x="142.9" y="69.3" transform="rotate(-90 142.9 69.3)">MOSI</text>
<text x="145.4" y="69.3" transform="rotate(-90 145.4 69.3)">MISO</text>
<text x="148" y="69.3" transform="rotate(-90 148 69.3)">SD_CS_LCD</text>
<text x="150.5" y="69.3" transform="rotate(-90 150.5 69.3)">SCK</text>
<text x="153" y="69.3" transform="rotate(-90 153 69.3)">DIR_E0</text>
<text x="155.6" y="69.3" transform="rotate(-90 155.6 69.3)">IO4</text>
<text x="158.1" y="69.3" transform="rotate(-90 158.1 69.3)">SD_MOSI</text>
<text x="160.7" y="69.3" transform="rotate(-90 160.7 69.3)">SD_MISO</text>
<text x="163.2" y="69.3" transform="rotate(-90 163.2 69.3)">SD_SCK</text>
<text x="165.7" y="69.3" transform="rotate(-90 165.7 69.3)">SD_CS</text>
<text x="168.3" y="69.3" transform="rotate(-90 168.3 69.3)">IO5</text>
<text x="170.8" y="69.3" transform="rotate(-90 170.8 69.3)">IO6</text>
<text x="173.4" y="69.3" transform="rotate(-90 173.4 69.3)">URX0</text>
<text x="175.9" y="69.3" transform="rotate(-90 175.9 69.3)">UTX0</text>
<text x="178.4" y="69.3" transform="rotate(-90 178.4 69.3)">IO3</text>
<text x="181" y="69.3" transform="rotate(-90 181 69.3)">IO2</text>
<text x="73.4" y="73" transform="rotate(-90 73.4 73)">18</text>
<text x="75.9" y="73" transform="rotate(-90 75.9 73)">16</text>
<text x="78.5" y="73" transform="rotate(-90 78.5 73)">23</text>
<text x="81" y="73" transform="rotate(-90 81 73)">22</text>
<text x="86.1" y="73" transform="rotate(-90 86.1 73)">14</text>
<text x="88.6" y="73" transform="rotate(-90 88.6 73)">17</text>
<text x="93.7" y="72.5" transform="rotate(-90 93.7 72.5)">5</text>
<text x="96.3" y="72.5" transform="rotate(-90 96.3 72.5)">4</text>
<text x="98.8" y="72.5" transform="rotate(-90 98.8 72.5)">3</text>
<text x="101.3" y="72.5" transform="rotate(-90 101.3 72.5)">2</text>
<text x="103.9" y="72.5" transform="rotate(-90 103.9 72.5)">1</text>
<text x="106.4" y="73.5" transform="rotate(-90 106.4 73.5)">100</text>
<text x="111.5" y="73" transform="rotate(-90 111.5 73)">30</text>
<text x="114" y="73" transform="rotate(-90 114 73)">29</text>
<text x="116.6" y="73" transform="rotate(-90 116.6 73)">24</text>
<text x="119.1" y="73" transform="rotate(-90 119.1 73)">25</text>
<text x="121.7" y="72.5" transform="rotate(-90 121.7 72.5)">6</text>
<text x="124.2" y="72.5" transform="rotate(-90 124.2 72.5)">7</text>
<text x="126.7" y="72.5" transform="rotate(-90 126.7 72.5)">8</text>
<text x="129.3" y="72.5" transform="rotate(-90 129.3 72.5)">9</text>
<text x="131.8" y="73" transform="rotate(-90 131.8 73)">56</text>
<text x="134.4" y="73" transform="rotate(-90 134.4 73)">57</text>
<text x="136.9" y="73" transform="rotate(-90 136.9 73)">58</text>
<text x="139.4" y="73" transform="rotate(-90 139.4 73)">59</text>
<text x="142" y="73" transform="rotate(-90 142 73)">60</text>
<text x="144.5" y="73" transform="rotate(-90 144.5 73)">61</text>
<text x="147.1" y="73" transform="rotate(-90 147.1 73)">63</text>
<text x="149.6" y="73" transform="rotate(-90 149.6 73)">62</text>
<text x="152.1" y="73" transform="rotate(-90 152.1 73)">49</text>
<text x="154.7" y="73" transform="rotate(-90 154.7 73)">48</text>
<text x="157.2" y="73" transform="rotate(-90 157.2 73)">76</text>
<text x="159.8" y="73" transform="rotate(-90 159.8 73)">77</text>
<text x="162.3" y="73" transform="rotate(-90 162.3 73)">78</text>
<text x="164.8" y="73" transform="rotate(-90 164.8 73)">79</text>
<text x="167.4" y="73" transform="rotate(-90 167.4 73)">80</text>
<text x="169.9" y="73" transform="rotate(-90 169.9 73)">81</text>
<text x="172.5" y="73" transform="rotate(-90 172.5 73)">99</text>
<text x="175" y="73" transform="rotate(-90 175 73)">98</text>
<text x="177.5" y="73" transform="rotate(-90 177.5 73)">47</text>
<text x="180.1" y="73" transform="rotate(-90 180.1 73)">46</text>
<text x="61.9" y="82.5">31</text>
<text x="185.1" y="82.5">28</text>
<text x="10.4" y="85.9">B</text>
<text x="61.9" y="85.1">41</text>
<text x="61.9" y="87.6">55</text>
<text x="185.1" y="85.1">54</text>
<text x="185.1" y="87.6">71</text>
<text x="285.4" y="85.9">B</text>
<text x="61.9" y="90.2">72</text>
<text x="61.9" y="92.7">83</text>
<text x="61.9" y="95.2">97</text>
<text x="185.1" y="92.7">42</text>
<text x="185.1" y="95.2">84</text>
<text x="185.1" y="90.2">96</text>
<text x="61.9" y="100.3">11</text>
<text x="61.9" y="97.8">15</text>
<text x="185.1" y="100.3">12</text>
<text x="185.1" y="97.8">19</text>
<text x="243.6" y="99.8" transform="rotate(-90 243.6 99.8)">3</text>
<text x="185.1" y="102.9">10</text>
<text x="225.5" y="103.8">USB_CONN</text>
<text x="237" y="102.9">1</text>
<text x="243.6" y="107.4" transform="rotate(-90 243.6 107.4)">2</text>
<text x="258" y="107.9">1</text>
<text x="258" y="110.5">2</text>
<text x="68.3" y="114.9" transform="rotate(-90 68.3 114.9)">85</text>
<text x="69.2" y="119.5" transform="rotate(-90 69.2 119.5)">IO8</text>
<text x="70.9" y="114.9" transform="rotate(-90 70.9 114.9)">82</text>
<text x="71.8" y="119.5" transform="rotate(-90 71.8 119.5)">IO7</text>
<text x="75.9" y="114.9" transform="rotate(-90 75.9 114.9)">26</text>
<text x="78.5" y="114.9" transform="rotate(-90 78.5 114.9)">27</text>
<text x="83.6" y="114.9" transform="rotate(-90 83.6 114.9)">50</text>
<text x="86.1" y="114.9" transform="rotate(-90 86.1 114.9)">51</text>
<text x="88.6" y="114.9" transform="rotate(-90 88.6 114.9)">52</text>
<text x="91.2" y="114.9" transform="rotate(-90 91.2 114.9)">53</text>
<text x="93.7" y="114.9" transform="rotate(-90 93.7 114.9)">64</text>
<text x="96.3" y="114.9" transform="rotate(-90 96.3 114.9)">65</text>
<text x="98.8" y="114.9" transform="rotate(-90 98.8 114.9)">66</text>
<text x="101.3" y="114.9" transform="rotate(-90 101.3 114.9)">67</text>
<text x="103.9" y="114.9" transform="rotate(-90 103.9 114.9)">68</text>
<text x="106.4" y="114.9" transform="rotate(-90 106.4 114.9)">69</text>
<text x="109" y="114.9" transform="rotate(-90 109 114.9)">70</text>
<text x="111.5" y="114.9" transform="rotate(-90 111.5 114.9)">73</text>
<text x="114" y="114.9" transform="rotate(-90 114 114.9)">74</text>
<text x="116.6" y="114.9" transform="rotate(-90 116.6 114.9)">75</text>
<text x="117.5" y="120" transform="rotate(-90 117.5 120)">SV1</text>
<text x="121.7" y="114.9" transform="rotate(-90 121.7 114.9)">20</text>
<text x="124.2" y="114.9" transform="rotate(-90 124.2 114.9)">21</text>
<text x="126.7" y="114.9" transform="rotate(-90 126.7 114.9)">45</text>
<text x="129.3" y="114.9" transform="rotate(-90 129.3 114.9)">44</text>
<text x="131.8" y="114.9" transform="rotate(-90 131.8 114.9)">43</text>
<text x="134.4" y="114.9" transform="rotate(-90 134.4 114.9)">40</text>
<text x="136.9" y="114.9" transform="rotate(-90 136.9 114.9)">39</text>
<text x="139.4" y="114.9" transform="rotate(-90 139.4 114.9)">38</text>
<text x="142" y="114.9" transform="rotate(-90 142 114.9)">37</text>
<text x="144.5" y="114.9" transform="rotate(-90 144.5 114.9)">36</text>
<text x="147.1" y="114.9" transform="rotate(-90 147.1 114.9)">35</text>
<text x="149.6" y="114.9" transform="rotate(-90 149.6 114.9)">34</text>
<text x="152.1" y="114.9" transform="rotate(-90 152.1 114.9)">33</text>
<text x="154.7" y="114.9" transform="rotate(-90 154.7 114.9)">32</text>
<text x="157.2" y="114.9" transform="rotate(-90 157.2 114.9)">86</text>
<text x="158.1" y="119.5" transform="rotate(-90 158.1 119.5)">IO9</text>
<text x="159.8" y="114.9" transform="rotate(-90 159.8 114.9)">87</text>
<text x="162.3" y="114.9" transform="rotate(-90 162.3 114.9)">88</text>
<text x="164.8" y="114.9" transform="rotate(-90 164.8 114.9)">89</text>
<text x="167.4" y="114.9" transform="rotate(-90 167.4 114.9)">90</text>
<text x="168.3" y="120" transform="rotate(-90 168.3 120)">S_X</text>
<text x="169.9" y="114.9" transform="rotate(-90 169.9 114.9)">91</text>
<text x="170.8" y="120" transform="rotate(-90 170.8 120)">S_Y</text>
<text x="172.5" y="114.9" transform="rotate(-90 172.5 114.9)">92</text>
<text x="173.4" y="119.9" transform="rotate(-90 173.4 119.9)">S_Z</text>
<text x="175" y="114.9" transform="rotate(-90 175 114.9)">93</text>
<text x="177.5" y="114.9" transform="rotate(-90 177.5 114.9)">94</text>
<text x="180.1" y="114.9" transform="rotate(-90 180.1 114.9)">95</text>
<text x="227.1" y="119">USB_D+</text>
<text x="258" y="115.6">1</text>
<text x="258" y="118.1">2</text>
<text x="76.8" y="124.7" transform="rotate(-90 76.8 124.7)">BTN_EN1</text>
<text x="79.4" y="124.7" transform="rotate(-90 79.4 124.7)">BTN_EN2</text>
<text x="84.5" y="124.4" transform="rotate(-90 84.5 124.4)">STEP_E0</text>
<text x="87" y="122.2" transform="rotate(-90 87 122.2)">EN_E0</text>
<text x="89.5" y="121.7" transform="rotate(-90 89.5 121.7)">DIR_Z</text>
<text x="97.2" y="121.2" transform="rotate(-90 97.2 121.2)">EN_Y</text>
<text x="99.7" y="120.9" transform="rotate(-90 99.7 120.9)">FET3</text>
<text x="102.2" y="121.8" transform="rotate(-90 102.2 121.8)">DIR_X</text>
<text x="104.8" y="120.9" transform="rotate(-90 104.8 120.9)">FET1</text>
<text x="107.3" y="120.9" transform="rotate(-90 107.3 120.9)">FET4</text>
<text x="109.9" y="120.9" transform="rotate(-90 109.9 120.9)">FET2</text>
<text x="112.4" y="123.4" transform="rotate(-90 112.4 123.4)">STEP_X</text>
<text x="114.9" y="121.2" transform="rotate(-90 114.9 121.2)">EN_X</text>
<text x="125.1" y="122.6" transform="rotate(-90 125.1 122.6)">Beeper</text>
<text x="127.6" y="121.5" transform="rotate(-90 127.6 121.5)">Z-MIN</text>
<text x="130.2" y="121.6" transform="rotate(-90 130.2 121.6)">Y-MIN</text>
<text x="132.7" y="121.6" transform="rotate(-90 132.7 121.6)">X-MIN</text>
<text x="135.3" y="122.2" transform="rotate(-90 135.3 122.2)">Z-MAX</text>
<text x="137.8" y="122.3" transform="rotate(-90 137.8 122.3)">Y-MAX</text>
<text x="140.3" y="122.3" transform="rotate(-90 140.3 122.3)">X-MAX</text>
<text x="142.9" y="121.2" transform="rotate(-90 142.9 121.2)">LCD7</text>
<text x="145.4" y="121.2" transform="rotate(-90 145.4 121.2)">LCD6</text>
<text x="148" y="121.2" transform="rotate(-90 148 121.2)">LCD5</text>
<text x="150.5" y="121.2" transform="rotate(-90 150.5 121.2)">LCD4</text>
<text x="153" y="122.7" transform="rotate(-90 153 122.7)">LCDRS</text>
<text x="155.6" y="121.4" transform="rotate(-90 155.6 121.4)">LCDE</text>
<text x="160.7" y="122.2" transform="rotate(-90 160.7 122.2)">EN_E1</text>
<text x="163.2" y="124.4" transform="rotate(-90 163.2 124.4)">STEP_E1</text>
<text x="165.7" y="122.8" transform="rotate(-90 165.7 122.8)">DIR_E1</text>
<text x="175.9" y="120.9" transform="rotate(-90 175.9 120.9)">S_E0</text>
<text x="178.4" y="120.9" transform="rotate(-90 178.4 120.9)">S_E1</text>
<text x="181" y="120.4" transform="rotate(-90 181 120.4)">IO10</text>
<text x="227.6" y="121.5">USB_D-</text>
<text x="258" y="120.6">3</text>
<text x="258" y="123.2">4</text>
<text x="92.1" y="130.9" transform="rotate(-90 92.1 130.9)">IO1</text>
<text x="94.6" y="126.5" transform="rotate(-90 94.6 126.5)">USB_CONN</text>
<text x="122.6" y="127.1" transform="rotate(-90 122.6 127.1)">SD_DETECT</text>
<text x="10.4" y="135.9">C</text>
<text x="39.1" y="135.4" transform="rotate(-90 39.1 135.4)">9</text>
<text x="44.2" y="135.4" transform="rotate(-90 44.2 135.4)">8</text>
<text x="285.4" y="135.9">C</text>
<text x="32.5" y="143.5">1</text>
<text x="50.3" y="141">2</text>
<text x="50.3" y="143.5">3</text>
<text x="12.8" y="144.4">SD_DETECT</text>
<text x="49.8" y="148.6">13</text>
<text x="49.8" y="146">14</text>
<text x="60.5" y="149.5">Beeper</text>
<text x="137.3" y="145.7">IO5</text>
<text x="137.3" y="148.2">IO6</text>
<text x="142.4" y="144.8">1</text>
<text x="142.4" y="147.3">2</text>
<text x="142.4" y="149.9">3</text>
<text x="160.2" y="148.2">IO4</text>
<text x="160.2" y="145.7">IO1</text>
<text x="165.3" y="144.8">1</text>
<text x="165.3" y="147.3">2</text>
<text x="165.3" y="149.9">3</text>
<text x="32.1" y="151.1">15</text>
<text x="32.1" y="153.7">16</text>
<text x="49.8" y="153.7">11</text>
<text x="49.8" y="151.1">12</text>
<text x="60.5" y="152">BTN_SW</text>
<text x="137.3" y="153.3">IO8</text>
<text x="137.3" y="150.7">IO7</text>
<text x="137.3" y="155.8">IO9</text>
<text x="142.4" y="152.4">4</text>
<text x="142.4" y="154.9">5</text>
<text x="160.2" y="153.3">IO2</text>
<text x="160.2" y="150.7">IO3</text>
<text x="165.3" y="152.4">4</text>
<text x="50.3" y="156.2">4</text>
<text x="50.3" y="158.7">5</text>
<text x="50.3" y="161.3">6</text>
<text x="70.6" y="159.6">MISO</text>
<text x="75.7" y="157.1">SCK</text>
<text x="136.3" y="160.9">IO11</text>
<text x="136.3" y="158.4">IO10</text>
<text x="142.4" y="157.5">6</text>
<text x="142.4" y="160">7</text>
<text x="50.3" y="163.8">7</text>
<text x="60.5" y="164.7">SD_CS_LCD</text>
<text x="65.6" y="162.2">MOSI</text>
<text x="127.2" y="167.6">1</text>
<text x="41.7" y="173.9" transform="rotate(-90 41.7 173.9)">10</text>
<text x="97.6" y="171.1">MISO</text>
<text x="97.6" y="168.5">MOSI</text>
<text x="98.3" y="173.6">SCK</text>
<text x="127.2" y="170.2">2</text>
<text x="127.2" y="172.7">3</text>
<text x="91.6" y="178.7">SD_DETECT</text>
<text x="91.6" y="176.1">SD_CS_LCD</text>
<text x="127.2" y="175.3">4</text>
<text x="127.2" y="177.8">5</text>
<text x="10.4" y="185.9">D</text>
<text x="127.2" y="180.3">6</text>
<text x="285.4" y="185.9">D</text>
<text x="35" y="199.9">1</text>
<text x="85" y="199.9">2</text>
<text x="135" y="199.9">3</text>
<text x="185" y="199.9">4</text>
<text x="235" y="199.9">5</text>
<text x="285" y="199.9">6</text>
</g>
<g font-size="1.8" fill="#008484">
<text x="114.9" y="16.9">+3.3V</text>
<text x="216.5" y="16.9">+3.3V</text>
<text x="32.3" y="19.4">+3.3V</text>
<text x="111.8" y="22.5">10K</text>
<text x="241.3" y="20.6">Micro_SD_Card_Det_Hirose_DM3AT</text>
<text x="255.1" y="18.3">J32</text>
<text x="21.6" y="25.2">C6</text>
<text x="21.8" y="27.5">0.1uF</text>
<text x="31.7" y="25.2">C7</text>
<text x="31.9" y="27.5">0.1uF</text>
<text x="41.9" y="25.2">C8</text>
<text x="42.1" y="27.5">0.1uF</text>
<text x="52.1" y="25.2">C9</text>
<text x="52.2" y="27.5">0.1uF</text>
<text x="62.3" y="25.2">C21</text>
<text x="62.4" y="27.5">0.1uF</text>
<text x="72.5" y="25.2">C11</text>
<text x="72.6" y="27.5">0.1uF</text>
<text x="82.6" y="25.2">C10</text>
<text x="82.7" y="27.5">0.1uF</text>
<text x="92.8" y="25.2">C23</text>
<text x="92.9" y="27.5">0.1uF</text>
<text x="112.9" y="24.8">R7</text>
<text x="221" y="27.4">R28</text>
<text x="221" y="25.1">10K</text>
<text x="227.4" y="27.4">R29</text>
<text x="227.4" y="25.1">10K</text>
<text x="239.8" y="28.8">DAT2</text>
<text x="32.5" y="33.3">GND</text>
<text x="119.5" y="31.5">C13</text>
<text x="119.6" y="33.8">0.1uF</text>
<text x="129.6" y="33.9">SW1</text>
<text x="239.8" y="31.4">DAT3/CD</text>
<text x="239.8" y="33.9">CMD</text>
<text x="129.6" y="36.2">SW_Push</text>
<text x="239.8" y="36.4">VDD</text>
<text x="239.8" y="39">CLK</text>
<text x="239.8" y="41.5">VSS</text>
<text x="73.1" y="46">GND</text>
<text x="82.9" y="45.5" transform="rotate(-90 82.9 45.5)">12pF</text>
<text x="85.2" y="45" transform="rotate(-90 85.2 45)">C17</text>
<text x="91.5" y="42.9">C14</text>
<text x="91.6" y="45.3">12pF</text>
<text x="122.6" y="44.7">GND</text>
<text x="218.5" y="46.7">10K</text>
<text x="224.8" y="46.7">10K</text>
<text x="239.8" y="44.1">DAT0</text>
<text x="239.8" y="46.6">DAT1</text>
<text x="79.9" y="51">12Mhz</text>
<text x="81.5" y="48.7">Y1</text>
<text x="218.5" y="49">R30</text>
<text x="224.8" y="49">R31</text>
<text x="239.8" y="49.1">DET_A</text>
<text x="239.8" y="51.7">DET_B</text>
<text x="266.8" y="51.7">SHIELD</text>
<text x="248.4" y="65">GND</text>
<text x="102.2" y="77.8" transform="rotate(-90 102.2 77.8)">TDI</text>
<text x="196.2" y="77.8">+3.3V</text>
<text x="65.8" y="83.4">VSS</text>
<text x="74.3" y="80.7" transform="rotate(-90 74.3 80.7)">RTCX2</text>
<text x="76.8" y="80.7" transform="rotate(-90 76.8 80.7)">RTCX1</text>
<text x="79.4" y="80.5" transform="rotate(-90 79.4 80.5)">XTAL2</text>
<text x="81.9" y="80.5" transform="rotate(-90 81.9 80.5)">XTAL1</text>
<text x="87" y="82.2" transform="rotate(-90 87 82.2)">RSTOUT</text>
<text x="89.5" y="80.8" transform="rotate(-90 89.5 80.8)">RESET</text>
<text x="97.2" y="79.5" transform="rotate(-90 97.2 79.5)">TRST</text>
<text x="104.8" y="83.4" transform="rotate(-90 104.8 83.4)">TDO/SWO</text>
<text x="107.3" y="79.8" transform="rotate(-90 107.3 79.8)">RTCK</text>
<text x="112.4" y="80.2" transform="rotate(-90 112.4 80.2)">P0[30]</text>
<text x="114.9" y="80.2" transform="rotate(-90 114.9 80.2)">P0[29]</text>
<text x="117.5" y="80.2" transform="rotate(-90 117.5 80.2)">P0[28]</text>
<text x="120" y="80.2" transform="rotate(-90 120 80.2)">P0[27]</text>
<text x="122.6" y="80.2" transform="rotate(-90 122.6 80.2)">P0[26]</text>
<text x="125.1" y="80.2" transform="rotate(-90 125.1 80.2)">P0[25]</text>
<text x="127.6" y="80.2" transform="rotate(-90 127.6 80.2)">P0[24]</text>
<text x="130.2" y="80.2" transform="rotate(-90 130.2 80.2)">P0[23]</text>
<text x="132.7" y="80.2" transform="rotate(-90 132.7 80.2)">P0[22]</text>
<text x="135.3" y="80.2" transform="rotate(-90 135.3 80.2)">P0[21]</text>
<text x="137.8" y="80.2" transform="rotate(-90 137.8 80.2)">P0[20]</text>
<text x="140.3" y="80.2" transform="rotate(-90 140.3 80.2)">P0[19]</text>
<text x="142.9" y="80.2" transform="rotate(-90 142.9 80.2)">P0[18]</text>
<text x="145.4" y="80.2" transform="rotate(-90 145.4 80.2)">P0[17]</text>
<text x="148" y="80.2" transform="rotate(-90 148 80.2)">P0[16]</text>
<text x="150.5" y="80.2" transform="rotate(-90 150.5 80.2)">P0[15]</text>
<text x="153" y="80.2" transform="rotate(-90 153 80.2)">P0[11]</text>
<text x="155.6" y="80.2" transform="rotate(-90 155.6 80.2)">P0[10]</text>
<text x="158.1" y="79.2" transform="rotate(-90 158.1 79.2)">P0[9]</text>
<text x="160.7" y="79.2" transform="rotate(-90 160.7 79.2)">P0[8]</text>
<text x="163.2" y="79.2" transform="rotate(-90 163.2 79.2)">P0[7]</text>
<text x="165.7" y="79.2" transform="rotate(-90 165.7 79.2)">P0[6]</text>
<text x="168.3" y="79.2" transform="rotate(-90 168.3 79.2)">P0[5]</text>
<text x="170.8" y="79.2" transform="rotate(-90 170.8 79.2)">P0[4]</text>
<text x="173.4" y="79.2" transform="rotate(-90 173.4 79.2)">P0[3]</text>
<text x="175.1" y="83.4">VDD(3V3)</text>
<text x="175.9" y="79.2" transform="rotate(-90 175.9 79.2)">P0[2]</text>
<text x="178.4" y="79.2" transform="rotate(-90 178.4 79.2)">P0[1]</text>
<text x="181" y="79.2" transform="rotate(-90 181 79.2)">P0[0]</text>
<text x="65.8" y="86">VSS</text>
<text x="65.8" y="88.5">VSS</text>
<text x="94.6" y="86.8" transform="rotate(-90 94.6 86.8)">TCK/SWDCLK</text>
<text x="99.7" y="85.1" transform="rotate(-90 99.7 85.1)">TMS/SWDIO</text>
<text x="175.1" y="86">VDD(3V3)</text>
<text x="175.1" y="88.5">VDD(3V3)</text>
<text x="44.9" y="94.8">LPC1768FBD100</text>
<text x="57.4" y="92.5">U2</text>
<text x="65.8" y="91.1">VSS</text>
<text x="65.8" y="93.6">VSS</text>
<text x="170.1" y="93.6">VDD(REG)(3V3)</text>
<text x="175.1" y="91.1">VDD(3V3)</text>
<text x="241.9" y="94.3">+3.3V</text>
<text x="65.8" y="101.2">VSSA</text>
<text x="65.8" y="98.7">VREFN</text>
<text x="65.8" y="96.1">VSS</text>
<text x="170.1" y="96.1">VDD(REG)(3V3)</text>
<text x="177.2" y="101.2">VREFP</text>
<text x="178.3" y="98.7">VBAT</text>
<text x="192.6" y="99.2" transform="rotate(-90 192.6 99.2)">L2</text>
<text x="194.9" y="99" transform="rotate(-90 194.9 99)">22uH</text>
<text x="255.3" y="99.4">+5V</text>
<text x="57.9" y="106.9">GND</text>
<text x="178.1" y="103.8">VDDA</text>
<text x="193.1" y="105.2">C12</text>
<text x="193.2" y="107.5">0.1uF</text>
<text x="246.7" y="102.6">Q5</text>
<text x="247" y="104.9">IRLML2244</text>
<text x="69.2" y="111" transform="rotate(-90 69.2 111)">P4[29]</text>
<text x="71.8" y="111" transform="rotate(-90 71.8 111)">P4[28]</text>
<text x="76.8" y="111" transform="rotate(-90 76.8 111)">P3[26]</text>
<text x="79.4" y="111" transform="rotate(-90 79.4 111)">P3[25]</text>
<text x="84.5" y="111" transform="rotate(-90 84.5 111)">P2[13]</text>
<text x="87" y="111" transform="rotate(-90 87 111)">P2[12]</text>
<text x="89.5" y="111" transform="rotate(-90 89.5 111)">P2[11]</text>
<text x="92.1" y="111" transform="rotate(-90 92.1 111)">P2[10]</text>
<text x="94.6" y="111" transform="rotate(-90 94.6 111)">P2[9]</text>
<text x="97.2" y="111" transform="rotate(-90 97.2 111)">P2[8]</text>
<text x="99.7" y="111" transform="rotate(-90 99.7 111)">P2[7]</text>
<text x="102.2" y="111" transform="rotate(-90 102.2 111)">P2[6]</text>
<text x="104.8" y="111" transform="rotate(-90 104.8 111)">P2[5]</text>
<text x="107.3" y="111" transform="rotate(-90 107.3 111)">P2[4]</text>
<text x="109.9" y="111" transform="rotate(-90 109.9 111)">P2[3]</text>
<text x="112.4" y="111" transform="rotate(-90 112.4 111)">P2[2]</text>
<text x="114.9" y="111" transform="rotate(-90 114.9 111)">P2[1]</text>
<text x="117.5" y="111" transform="rotate(-90 117.5 111)">P2[0]</text>
<text x="122.6" y="111" transform="rotate(-90 122.6 111)">P1[31]</text>
<text x="125.1" y="111" transform="rotate(-90 125.1 111)">P1[30]</text>
<text x="127.6" y="111" transform="rotate(-90 127.6 111)">P1[29]</text>
<text x="130.2" y="111" transform="rotate(-90 130.2 111)">P1[28]</text>
<text x="132.7" y="111" transform="rotate(-90 132.7 111)">P1[27]</text>
<text x="135.3" y="111" transform="rotate(-90 135.3 111)">P1[26]</text>
<text x="137.8" y="111" transform="rotate(-90 137.8 111)">P1[25]</text>
<text x="140.3" y="111" transform="rotate(-90 140.3 111)">P1[24]</text>
<text x="142.9" y="111" transform="rotate(-90 142.9 111)">P1[23]</text>
<text x="145.4" y="111" transform="rotate(-90 145.4 111)">P1[22]</text>
<text x="148" y="111" transform="rotate(-90 148 111)">P1[21]</text>
<text x="150.5" y="111" transform="rotate(-90 150.5 111)">P1[20]</text>
<text x="153" y="111" transform="rotate(-90 153 111)">P1[19]</text>
<text x="155.6" y="111" transform="rotate(-90 155.6 111)">P1[18]</text>
<text x="158.1" y="111" transform="rotate(-90 158.1 111)">P1[17]</text>
<text x="160.7" y="111" transform="rotate(-90 160.7 111)">P1[16]</text>
<text x="163.2" y="111" transform="rotate(-90 163.2 111)">P1[15]</text>
<text x="165.7" y="111" transform="rotate(-90 165.7 111)">P1[14]</text>
<text x="168.3" y="111" transform="rotate(-90 168.3 111)">P1[10]</text>
<text x="170.8" y="111" transform="rotate(-90 170.8 111)">P1[9]</text>
<text x="173.4" y="111" transform="rotate(-90 173.4 111)">P1[8]</text>
<text x="175.9" y="111" transform="rotate(-90 175.9 111)">P1[4]</text>
<text x="178.4" y="111" transform="rotate(-90 178.4 111)">P1[1]</text>
<text x="181" y="111" transform="rotate(-90 181 111)">P1[0]</text>
<text x="188.7" y="113.3">GND</text>
<text x="238.8" y="112.5">R32</text>
<text x="238.8" y="110.2">1K5</text>
<text x="263.8" y="111.4">USB_5V</text>
<text x="263.9" y="109.1">J22</text>
<text x="237" y="116.6" transform="rotate(-90 237 116.6)">R33</text>
<text x="239.3" y="116.6" transform="rotate(-90 239.3 116.6)">33K</text>
<text x="263.9" y="119.2">J21</text>
<text x="236.9" y="125.9" transform="rotate(-90 236.9 125.9)">33K</text>
<text x="239.2" y="125.9" transform="rotate(-90 239.2 125.9)">R34</text>
<text x="263.8" y="121.6">USB</text>
<text x="38.2" y="129.9">+5V</text>
<text x="82.6" y="129">R38</text>
<text x="82.6" y="126.7">10K</text>
<text x="235.8" y="127.9">12pF</text>
<text x="236.7" y="130.2">C57</text>
<text x="244.7" y="127.9">12pF</text>
<text x="245.6" y="130.2">C58</text>
<text x="85.8" y="134.9">GND</text>
<text x="254.7" y="137.4">GND</text>
<text x="40" y="138.8" transform="rotate(-90 40 138.8)">5V</text>
<text x="45.1" y="139.8" transform="rotate(-90 45.1 139.8)">3V3</text>
<text x="46.8" y="141.9">A0</text>
<text x="26.3" y="149.7">R46</text>
<text x="26.5" y="147.4">470</text>
<text x="34.8" y="144.4">RST</text>
<text x="42.5" y="149.5">SDA/D2</text>
<text x="42.7" y="146.9">SCL/D1</text>
<text x="46.8" y="144.4">D0</text>
<text x="54.2" y="146.7">R49</text>
<text x="54.2" y="149">2K2</text>
<text x="171.2" y="148.5">J25</text>
<text x="19.4" y="151.7" transform="rotate(-90 19.4 151.7)">R50</text>
<text x="21.7" y="151.7" transform="rotate(-90 21.7 151.7)">2K2</text>
<text x="34.8" y="152">RX</text>
<text x="34.8" y="154.6">TX</text>
<text x="46.8" y="154.6">D4</text>
<text x="46.8" y="152">D3</text>
<text x="64.4" y="154.3">R45</text>
<text x="69.5" y="151.8">R43</text>
<text x="70.1" y="154.1">47</text>
<text x="148.3" y="152.3">J1</text>
<text x="148.3" y="154.6">EXP3</text>
<text x="171.2" y="150.8">EXP4</text>
<text x="41.8" y="159.6">MISO/D6</text>
<text x="42.5" y="157.1">SCK/D5</text>
<text x="54.2" y="159.4">R48</text>
<text x="54.2" y="161.7">2K2</text>
<text x="59.3" y="156.8">R44</text>
<text x="60" y="159.2">47</text>
<text x="65" y="156.6">47</text>
<text x="41.8" y="162.2">MOSI/D7</text>
<text x="43.8" y="164.7">CS/D8</text>
<text x="112.6" y="165.7">R39</text>
<text x="120.3" y="163.2">R51</text>
<text x="120.4" y="165.5">100</text>
<text x="42.5" y="171.2" transform="rotate(-90 42.5 171.2)">GND</text>
<text x="105" y="168.3">R40</text>
<text x="105.2" y="170.6">100</text>
<text x="112.6" y="173.3">R42</text>
<text x="112.8" y="168">100</text>
<text x="120.3" y="170.8">R41</text>
<text x="120.4" y="173.1">100</text>
<text x="133.1" y="173.9">J26</text>
<text x="34.9" y="179.5">WeMos_D1_mini</text>
<text x="40.8" y="177.2">U9</text>
<text x="112.8" y="175.7">100</text>
<text x="133" y="176.2">PI</text>
<text x="40.1" y="185.7">GND</text>
<text x="122.6" y="186.9">GND</text>
</g>
</g></defs>
<g fill="none" stroke="#840000" stroke-width=".18">
<path d="M10 10.3h277v189.9h-277zM12 12.2h273v186.1h-273zM60 10.3v1.9M110 10.3v1.9M116.8 18v3.3M116.8 18l-.7 1.3M116.8 18l.8 1.3M160 10.3v1.9M210 10.3v1.9M218.4 18l-.7 1.3M218.4 18v2.6M218.4 18l.8 1.3"/>
<path d="M260 10.3v1.9M19 23.1v2M19 26.2v2M29.2 23.1v2M29.2 26.2v2M34.3 28.2v1.3h1.3l-1.3 1.2-1.3-1.2h1.3M34.3 20.6l-.8 1.2M34.3 20.6v2.5M34.3 20.6l.8 1.2M39.4 23.1v2M39.4 26.2v2M49.5 23.1v2"/>
<path d="M49.5 26.2v2M59.7 23.1v2M59.7 26.2v2M69.8 23.1v2M69.8 26.2v2M80 23.1v2M80 26.2v2M90.2 23.1v2M90.2 26.2v2M116.8 24.9v.7M116.8 29.5v2M116.8 32.5v2"/>
<path d="M124.5 39.6v1.3h1.2l-1.2 1.3-1.3-1.3h1.3M125.2 34.5h1.8M127 32v5.1M128.3 29.5v2.5M128.3 37.1v2.5M226.1 23.1v.8M226.1 27.4v.8M232.4 23.1v.8M232.4 27.4v.8M234.9 28.2h3.9M234.9 30.7h3.9M234.9 33.3h3.9"/>
<path d="M234.9 35.8h3.9M234.9 38.3h3.9M74.9 40.9v1.3h1.3l-1.3 1.2-1.2-1.2h1.2M78.7 40.9v2M78.7 43.9v2.1M78.7 54.9h1.9M84.5 54.9h1.9M88.9 40.9v2M88.9 43.9v2.1M223.5 44.7v.8M223.5 49v.8M229.9 44.7v.8"/>
<path d="M229.9 49v.8M234.9 48.5h3.9M234.9 51h3.9M234.9 40.9h3.9M234.9 43.4h3.9M234.9 46h3.9M250.2 59.9v1.3h1.3l-1.3 1.3-1.3-1.3h1.3M274.3 51h3.8M10 60.2h2M73.7 70.1v3.8M76.2 70.1v3.8M78.7 70.1v3.8"/>
<path d="M81.3 70.1v3.8M86.4 70.1v3.8M88.9 70.1v3.8M94 70.1v3.8M96.5 70.1v3.8M99.1 70.1v3.8M101.6 70.1v3.8M104.1 70.1v3.8M106.7 70.1v3.8M111.8 70.1v3.8M111.8 61.9v1M114.3 70.1v3.8"/>
<path d="M116.8 70.1v3.8M119.4 70.1v3.8M121.9 70.1v3.8M122.5 65.1v.7M124.5 70.1v3.8M127 70.1v3.8M129.5 70.1v3.8M132.1 70.1v3.8M134.6 70.1v3.8M137.2 70.1v3.8M139.7 70.1v3.8M142.2 70.1v3.8"/>
<path d="M144.8 70.1v3.8M147.3 70.1v3.8M149.9 70.1v3.8M152.4 70.1v3.8M154.9 70.1v3.8M157.5 70.1v3.8M160 70.1v3.8M162.6 70.1v3.8M165.1 70.1v3.8M167.6 70.1v3.8M170.2 70.1v3.8M172.7 70.1v3.8"/>
<path d="M175.3 70.1v3.8M177.8 70.1v3.8M180.3 70.1v3.8M198.1 79l-.7 1.3M198.1 79v2.5M198.1 79l.8 1.3M285 60.2h2M61 98h3.8M61 82.8h3.8M61 85.3h3.8M61 93h3.8M61 87.9h3.8"/>
<path d="M61 90.4h3.8M61 95.5h3.8M184.1 98h3.9M184.1 82.8h3.9M184.1 85.3h3.9M184.1 93h3.9M184.1 87.9h3.9M184.1 90.4h3.9M184.1 95.5h3.9M243.8 95.5l-.7 1.3M243.8 95.5v5.8M243.8 95.5l.8 1.3"/>
<path d="M10 110.3h2M59.7 101.8v1.3h1.3l-1.3 1.3-1.3-1.3h1.3M61 100.6h3.8M68.6 112v3.8M71.1 112v3.8M76.2 112v3.8M78.7 112v3.8M83.8 112v3.8M86.4 112v3.8M88.9 112v3.8M91.4 112v3.8M94 112v3.8"/>
<path d="M96.5 112v3.8M99.1 112v3.8M101.6 112v3.8M104.1 112v3.8M106.7 112v3.8M109.2 112v3.8M111.8 112v3.8M114.3 112v3.8M116.8 112v3.8M121.9 112v3.8M124.5 112v3.8M127 112v3.8"/>
<path d="M129.5 112v3.8M132.1 112v3.8M134.6 112v3.8M137.2 112v3.8M139.7 112v3.8M142.2 112v3.8M144.8 112v3.8M147.3 112v3.8M149.9 112v3.8M152.4 112v3.8M154.9 112v3.8M157.5 112v3.8"/>
<path d="M160 112v3.8M162.6 112v3.8M165.1 112v3.8M167.6 112v3.8M170.2 112v3.8M172.7 112v3.8M175.3 112v3.8M177.8 112v3.8M180.3 112v3.8M184.1 100.6h3.9M184.1 103.1h3.9M190.5 106.2v3.3h1.3l-1.3 1.2-1.3-1.2h1.3"/>
<path d="M190.5 100.6h.5l.1-.4 .3-.1 .4 .1 .2 .4 .2-.4 .2-.1 .5 .1 .1 .4 .2-.4 .2-.1 .5 .1 .2 .4 .1-.4 .3-.1 .4 .1 .2 .4h.5M190.5 103.1v2.1M234.9 118.4h.8M236.2 103.1h5.4M239.3 118.4h.7M242.1 103.1h1.7v5.9M242.1 101.3h2.5v3.6h-2.5M243.8 112.5v.8M244.1 102.6l.1 .1h.8l.1 .2M244.6 102.7l.4 .7h-.8zM256.5 115.8h3.8M256.5 118.4h3.8"/>
<path d="M256.5 108.2h3.8M256.5 110.7h3.8M256.5 100.6l-.7 1.2M256.5 100.6v2.5M256.5 100.6l.8 1.2M260.3 115.7h1.3v.2h-1.3zM260.3 118.2h1.3v.3h-1.3zM260.3 110.6h1.3v.3h-1.3zM260.3 108.1h1.3v.2h-1.3zM285 110.3h2M39.4 131.1l-.8 1.2M39.4 131.1v5"/>
<path d="M39.4 131.1l.7 1.2M44.4 133.6v2.5M87.6 129v2.1h1.3l-1.3 1.2-1.2-1.2h1.2M87.6 124.7v.8M127.6 121.8v.9l-1.3-.9v.9M128.8 121.8l.7 .4-.7 .4M131.4 121.8l1.2 .9M132.6 121.8l-1.2 .9M135.2 122.2v.8l-1.3-.8v.8M136.4 122.1l.7 .4-.7 .5M139 122.2l1.3 .8M140.3 122.2l-1.3 .8"/>
<path d="M226.7 120.2v1l.3 .3 .4-.1 .1-.2v-1M234.9 120.9h.8M239.3 120.9h.7M242.6 126v2M242.6 129v2.1M251.5 126v2M251.5 129v2.1M256.5 132.3v1.3h1.3l-1.3 1.3-1.2-1.3h1.2M256.5 120.9h3.8M256.5 123.4h3.8M260.3 123.3h1.3v.3h-1.3zM260.3 120.8h1.3v.2h-1.3z"/>
<path d="M24.1 143.8h1.3M24.1 146.3v1.3M24.1 152.6v1.3M30.5 143.8h3.8M49.5 143.8h2.6M49.5 141.2h2.6M49.5 156.5h2.6M49.5 159h2.6M52.1 151.4h1.2M58.4 151.4h1.3M62.2 159h1.3M66.9 148.6l-.4 .2"/>
<path d="M67.3 156.5h1.3M68.6 159h1.2M73.7 156.5h1.2M141 145h3.8M141 147.6h3.8M141 150.1h3.8M141 152.6h3.8M141 155.2h3.8M141 157.7h3.8M144.8 157.6h1.2v.3h-1.2zM144.8 155.1h1.2v.2h-1.2zM144.8 150h1.2v.2h-1.2z"/>
<path d="M144.8 147.4h1.2v.3h-1.2zM144.8 144.9h1.2v.3h-1.2zM144.8 152.5h1.2v.3h-1.2zM163.8 145h3.8M163.8 147.6h3.8M163.8 150.1h3.8M163.8 152.6h3.8M167.6 152.5h1.3v.3h-1.3zM167.6 150h1.3v.2h-1.3zM167.6 144.9h1.3v.3h-1.3zM167.6 147.4h1.3v.3h-1.3zM10 160.2h2"/>
<path d="M49.5 161.5h2.6M49.5 164.1h3.8M57.1 161.5h1.3M58.4 164.1h1.3M63.5 161.5h1.3M102.9 173h1.2M109.2 173h1.3M110.5 170.4h1.3M110.5 178h1.3M116.8 170.4h1.3M116.8 178h1.3M118.1 167.9h1.3"/>
<path d="M118.1 175.5h1.3M124.5 167.9h5M124.5 175.5h5M125.7 170.4h3.8M125.7 173h3.8M125.7 178h3.8M129.5 177.9h1.3v.3h-1.3zM129.5 175.4h1.3v.2h-1.3zM129.5 170.3h1.3v.3h-1.3zM129.5 167.8h1.3v.2h-1.3zM129.5 172.8h1.3v.3h-1.3zM141 160.3h3.8"/>
<path d="M144.8 160.1h1.2v.3h-1.2zM177 166.3h108v32h-108zM285 160.2h2M41.9 180.6v1.3h1.3l-1.3 1.2-1.3-1.2h1.3M60 198.3v1.9M110 198.3v1.9M124.5 181.9v1.2h1.2l-1.2 1.3-1.3-1.3h1.3M125.7 180.6h3.8M129.5 180.5h1.3v.2h-1.3zM160 198.3v1.9M177 194.8h108M177 191.8h108"/>
<path d="M177 187.8h108M177 181.8h108M186.5 192.5l-.4 1h1M186.8 193v1M191.3 182.4v1.2l.3 .3h.2l.3-.3v-1.2M192.3 185.7h.1a.37 .37 0 0 1 .6 .1v.8M192.3 185.1v1.5M193.9 182.3l-1.3 2M197 191.8v3M204.7 196.8h.8M206.2 196.7v.1M207.7 196l-.1 .1a.48 .48 0 0 1-.6 .1l-.2-.2 .2-.6a.48 .48 0 0 1 .6 .1 1.27 1.27 0 0 1-.2 1.2l-.4 .1"/>
<path d="M208.2 195.1a1.71 1.71 0 0 1 0 2.3M209.3 196.3h1.2M210 198.3v1.9M211.1 195.8l.4-.5v1.5M211.1 196.8h.9M260 198.3v1.9M261 191.8v6.5M269.8 195.2l-1.2 2M270.2 195.3h.9l-.5 .6 .4 .1v.7l-.2 .1-.6-.1"/>
<circle cx="128.3" cy="32.5" r=".51"/>
<circle cx="128.3" cy="36.6" r=".51"/>
</g>
<path d="M116.1 21.3h1.5v3.6h-1.5zM225.3 23.9h1.5v3.5h-1.5zM231.6 23.9h1.6v3.5h-1.6zM222.8 45.5h1.5v3.5h-1.5zM229.1 45.5h1.5v3.5h-1.5zM235.7 117.6h3.6v1.5h-3.6zM243.1 109h1.5v3.5h-1.5zM86.9 125.5h1.5v3.5h-1.5zM235.7 120.1h3.6v1.6h-3.6z" fill="none" stroke="#840000" stroke-width=".2"/>
<g fill="#ffffc2" stroke="#ffffc2" stroke-width=".18">
<path d="M167.6 143.8h2.6v10.1h-2.6z"/>
<path d="M248.9 26.9h7.6l3.8-3.8h1.3v1.3h2.6l1.2-1.3h12.7v24.1h-29.2z"/>
<path d="M129.5 166.6h2.6v15.3h-2.6z"/>
<path d="M34.3 136.1h15.2v35.6h-15.2z"/>
<path d="M260.3 114.5h2.6v10.2h-2.6z"/>
<path d="M144.8 143.8h2.5v17.7h-2.5z"/>
<path d="M260.3 106.9h2.6v5.1h-2.6z"/>
<path d="M64.8 73.9h119.3v38.1h-119.3z"/>
</g>
<g fill="none" stroke="#840000" stroke-width=".25">
<path d="M103.5 28.3h6.4l.6 1.2-.6 1.1h-6.4zM213 32.2h8.6l.6 1.1-.6 1.1h-8.6zM213.8 37.2h7.8l.6 1.1-.6 1.2h-7.8zM215.1 29.6h6.5l.6 1.1-.6 1.1h-6.5zM248.9 26.9h7.6l3.8-3.8h1.3v1.3h2.6l1.2-1.3h12.7v24.1h-29.2zM274.3 23.1v-1.3h-35.5v33.1h35.5v-7.7M118.3 54.3h2.2v15.2l-1.1 .6-1.1-.6zM146.2 58.4h2.2v11.1l-1.1 .6-1.1-.6zM213 42.3h8.6l.6 1.1-.6 1.1h-8.6zM215.3 52.5h15.2l.6 1.1-.6 1.1h-15.2zM64.8 73.9h119.3v38.1h-119.3zM87.8 63.1h2.2v6.4l-1.1 .6-1.1-.6z"/>
<path d="M110.6 61.3h2.3v8.2l-1.1 .6-1.2-.6zM113.2 61.3h2.2v8.2l-1.1 .6-1.1-.6zM115.7 61.7h2.3v7.8l-1.2 .6-1.1-.6zM120.8 64.5h2.2v5l-1.1 .6-1.1-.6zM123.3 66.7h2.3v2.8l-1.1 .6-1.2-.6zM125.9 66.7h2.2v2.8l-1.1 .6-1.1-.6zM128.4 66.7h2.3v2.8l-1.2 .6-1.1-.6zM131 62.1h2.2v7.4l-1.1 .6-1.1-.6zM133.5 64.2h2.2v5.3l-1.1 .6-1.1-.6zM136 63.7h2.3v5.8l-1.1 .6-1.2-.6zM138.6 62.2h2.2v7.3l-1.1 .6-1.1-.6zM141.1 64.3h2.3v5.2l-1.2 .6-1.1-.6z"/>
<path d="M143.7 64.3h2.2v5.2l-1.1 .6-1.1-.6zM148.7 65.1h2.3v4.4l-1.1 .6-1.2-.6zM151.3 62.4h2.2v7.1l-1.1 .6-1.1-.6zM153.8 65.7h2.3v3.8l-1.2 .6-1.1-.6zM156.4 60.8h2.2v8.7l-1.1 .6-1.1-.6zM158.9 60.8h2.2v8.7l-1.1 .6-1.1-.6zM161.4 61.7h2.3v7.8l-1.1 .6-1.2-.6zM164 63h2.2v6.5l-1.1 .6-1.1-.6zM166.5 65.7h2.3v3.8l-1.2 .6-1.1-.6zM169.1 65.7h2.2v3.8l-1.1 .6-1.1-.6zM171.6 63.8h2.2v5.7l-1.1 .6-1.1-.6zM174.1 64.2h2.3v5.3l-1.1 .6-1.2-.6z"/>
<path d="M176.7 65.7h2.2v3.8l-1.1 .6-1.1-.6zM179.2 65.7h2.3v3.8l-1.2 .6-1.1-.6zM67.5 116.5l1.1-.7 1.1 .7v3.7h-2.2zM70 116.5l1.1-.7 1.1 .7v3.7h-2.2zM75.1 116.5l1.1-.7 1.1 .7v8.8h-2.2zM77.6 116.5l1.1-.7 1.2 .7v8.8h-2.3zM82.7 116.5l1.1-.7 1.1 .7v8.5h-2.2zM85.2 116.5l1.2-.7 1.1 .7v6.4h-2.3zM87.8 116.5l1.1-.7 1.1 .7v5.9h-2.2zM92.9 116.5l1.1-.7 1.1 .7v10.6h-2.2zM95.4 116.5l1.1-.7 1.1 .7v5.1h-2.2zM97.9 116.5l1.2-.7 1.1 .7v5h-2.3z"/>
<path d="M100.5 116.5l1.1-.7 1.1 .7v5.9h-2.2zM103 116.5l1.1-.7 1.2 .7v5h-2.3zM105.6 116.5l1.1-.7 1.1 .7v5h-2.2zM108.1 116.5l1.1-.7 1.1 .7v5h-2.2zM110.6 116.5l1.2-.7 1.1 .7v7.3h-2.3zM113.2 116.5l1.1-.7 1.1 .7v5.2h-2.2zM115.7 116.5l1.1-.7 1.2 .7v4h-2.3zM120.8 116.5l1.1-.7 1.1 .7v10.7h-2.2zM123.3 116.5l1.2-.7 1.1 .7v7h-2.3zM125.9 116.5l1.1-.7 1.1 .7v6.7h-2.2zM128.4 116.5l1.1-.7 1.2 .7v6.6h-2.3zM131 116.5l1.1-.7 1.1 .7v6.7h-2.2z"/>
<path d="M133.5 116.5l1.1-.7 1.1 .7v7.1h-2.2zM136 116.5l1.2-.7 1.1 .7v6.9h-2.3zM138.6 116.5l1.1-.7 1.1 .7v7.1h-2.2zM141.1 116.5l1.1-.7 1.2 .7v5.3h-2.3zM143.7 116.5l1.1-.7 1.1 .7v5.3h-2.2zM146.2 116.5l1.1-.7 1.1 .7v5.3h-2.2zM148.7 116.5l1.2-.7 1.1 .7v5.3h-2.3zM151.3 116.5l1.1-.7 1.1 .7v6.6h-2.2zM153.8 116.5l1.1-.7 1.2 .7v5.3h-2.3zM156.4 116.5l1.1-.7 1.1 .7v3.7h-2.2zM158.9 116.5l1.1-.7 1.1 .7v6.4h-2.2zM161.4 116.5l1.2-.7 1.1 .7v8.5h-2.3z"/>
<path d="M164 116.5l1.1-.7 1.1 .7v7h-2.2zM166.5 116.5l1.1-.7 1.2 .7v3.9h-2.3zM169.1 116.5l1.1-.7 1.1 .7v3.8h-2.2zM171.6 116.5l1.1-.7 1.1 .7v3.9h-2.2zM174.1 116.5l1.2-.7 1.1 .7v5.1h-2.3zM176.7 116.5l1.1-.7 1.1 .7v5.1h-2.2zM179.2 116.5l1.1-.7 1.2 .7v4.9h-2.3zM225 102h10.6l.6 1.1-.6 1.1h-10.6zM226.1 117.2h8.2l.6 1.2-.6 1.1h-8.2zM226.1 119.8h8.2l.6 1.1-.6 1.1h-8.2zM241.6 101.2v3.8M242.1 100.8v1"/>
<path d="M242.1 102.6v1M242.1 104.4v1M260.3 114.5h2.6v10.2h-2.6zM260.3 106.9h2.6v5.1h-2.6zM34.3 136.1h15.2v35.6h-15.2zM90.3 127.9l1.1-.7 1.2 .7v3.7h-2.3zM12.7 142.6h10.8l.6 1.2-.6 1.1h-10.8zM23.1 147.6h2v5h-2zM25.4 142.7h5.1v2.1h-5.1zM53.3 150.4h5.1v2h-5.1zM60.3 147.7h7.1v2.3h-7.1l-.6-1.2zM60.3 150.3h7.8v2.2h-7.8l-.6-1.1z"/>
<path d="M63.5 158h5.1v2h-5.1zM68.6 155.4h5.1v2.1h-5.1zM70.5 157.9h5.2v2.2h-5.2l-.7-1.1zM75.6 155.3h4.3v2.3h-4.3l-.7-1.1zM135.4 159.2h4.9l.7 1.1-.7 1.1h-4.9zM135.4 156.6h4.9l.7 1.1-.7 1.1h-4.9zM136.6 143.9h3.7l.7 1.1-.7 1.1h-3.7zM136.6 151.5h3.7l.7 1.1-.7 1.2h-3.7zM136.6 146.5h3.7l.7 1.1-.7 1.1h-3.7zM136.6 149h3.7l.7 1.1-.7 1.1h-3.7zM136.6 154.1h3.7l.7 1.1-.7 1.1h-3.7zM144.8 143.8h2.5v17.7h-2.5z"/>
<path d="M159.5 151.5h3.7l.6 1.1-.6 1.2h-3.7zM159.5 149h3.7l.6 1.1-.6 1.1h-3.7zM159.5 146.5h3.7l.6 1.1-.6 1.1h-3.7zM159.5 143.9h3.7l.6 1.1-.6 1.1h-3.7zM167.6 143.8h2.6v10.1h-2.6zM53.3 163.1h5.1v2h-5.1zM58.4 160.5h5.1v2.1h-5.1zM60.3 163h11.1v2.2h-11.1l-.6-1.1zM65.4 160.4h5.2v2.3h-5.2l-.6-1.2zM91.2 174.4h11l.7 1.1-.7 1.1h-11zM91.4 176.9h10.8l.7 1.1-.7 1.2h-10.8zM97.1 169.3h5.1l.7 1.1-.7 1.1h-5.1z"/>
<path d="M97.1 166.8h5.1l.7 1.1-.7 1.1h-5.1zM97.9 171.9h4.3l.7 1.1-.7 1.1h-4.3zM104.1 172h5.1v2h-5.1zM111.8 169.4h5v2h-5zM111.8 177h5v2.1h-5zM119.4 166.9h5.1v2h-5.1zM119.4 174.5h5.1v2h-5.1zM129.5 166.6h2.6v15.3h-2.6z"/>
<circle cx="243" cy="103.1" r="2.79"/>
</g>
<g fill="none" stroke="#840000" stroke-width=".33">
<path d="M17.5 26.2h3.1M27.7 26.2h3M37.8 26.2h3.1M48 26.2h3.1M58.2 26.2h3M68.3 26.2h3.1M78.5 26.2h3M88.6 26.2h3.1M115.3 32.5h3.1M77.2 43.9h3.1M87.4 43.9h3M189 106.2h3"/>
<path d="M241 128h3.1M249.9 128h3.1"/>
</g>
<g fill="none" stroke="#840000" stroke-width=".3">
<path d="M17.5 25.1h3.1M27.7 25.1h3M37.8 25.1h3.1M48 25.1h3.1M58.2 25.1h3M68.3 25.1h3.1M78.5 25.1h3M88.6 25.1h3.1M115.3 31.5h3.1M77.2 42.9h3.1M81.4 52.3h2.3v5.1h-2.3zM87.4 42.9h3"/>
<path d="M189 105.2h3M241 129h3.1M249.9 129h3.1"/>
</g>
<path d="M80.6 53.6v2.5M84.5 53.6v2.5" fill="none" stroke="#840000" stroke-width=".51"/>
<g fill="#840000" stroke="#840000" stroke-width=".18">
<path d="M250.2 45.3h2.5v1.3h-2.5z"/>
<path d="M250.2 42.8h2.5v1.3h-2.5z"/>
<path d="M250.2 40.3h2.5v1.2h-2.5z"/>
<path d="M250.2 37.7h2.5v1.3h-2.5z"/>
<path d="M250.2 35.2h2.5v1.2h-2.5z"/>
<path d="M250.2 32.6h2.5v1.3h-2.5z"/>
<path d="M250.2 30.1h2.5v1.3h-2.5z"/>
<path d="M250.2 27.6h2.5v1.2h-2.5z"/>
<path d="M242.3 103.1l1-.4v.8z"/>
<circle cx="243.8" cy="104.9" r=".25"/>
<circle cx="243.8" cy="101.3" r=".25"/>
</g>
<g fill="none" stroke="#008484" stroke-width=".18">
<path d="M271.6 19.2h.7M272 19.2v1.3M247.3 30a.64 .64 0 0 1 .7 .7 .64 .64 0 0 1-.7 .6zM270.5 20.5l.4-1.3 .4 1.3M44.4 93.4v1.3h.6M58.9 93.6l.2-.2a.69 .69 0 0 1 .4 .7 .69 .69 0 0 1-.4 .6l-.2-.2-.1-.3zM111.7 81.3v-.6l-.5-.1-.2 .2v.5h1.3M114.2 81.3v-.6l-.5-.1-.1 .2v.5h1.3M116.8 81.3l-.1-.6-.4-.1-.2 .2v.5h1.3M119.3 81.3v-.6l-.5-.1-.1 .2v.5h1.2M121.9 81.3l-.1-.6-.5-.1-.1 .2v.5h1.3M124.4 81.3v-.6l-.5-.1-.2 .2v.5h1.3"/>
<path d="M126.9 81.3v-.6l-.5-.1-.1 .2v.5h1.3M129.5 81.3l-.1-.6-.4-.1-.2 .2v.5h1.3M132 81.3v-.6l-.5-.1-.1 .2v.5h1.2M134.6 81.3l-.1-.6-.5-.1-.1 .2v.5h1.3M137.1 81.3v-.6l-.5-.1-.2 .2v.5h1.3M139.6 81.3v-.6l-.5-.1-.1 .2v.5h1.3M142.2 81.3l-.1-.6-.4-.1-.2 .2v.5h1.3M144.7 81.3v-.6l-.5-.1-.1 .2v.5h1.2M147.3 81.3l-.1-.6-.5-.1-.1 .2v.5h1.3M149.8 81.3v-.6l-.5-.1-.2 .2v.5h1.3M152.3 81.3v-.6l-.5-.1-.1 .2v.5h1.3M154.9 81.3l-.1-.6-.4-.1-.2 .2v.5h1.3"/>
<path d="M157.4 80.1l-.1-.7h-.4l-.1 .2v.5h1.2M160 80.1l-.1-.7h-.5l-.1 .2v.5h1.3M162.5 80.1l-.1-.7h-.4l-.2 .2v.5h1.3M165 80.1l-.1-.7h-.4l-.1 .2v.5h1.3M167.6 80.1l-.1-.7h-.4l-.2 .2v.5h1.3M169 92.2l.4 1.3 .4-1.3M169 94.8l.4 1.3 .4-1.3M170.1 80.1l-.1-.7h-.4l-.1 .2v.5h1.2M172.7 80.1l-.1-.7h-.5l-.1 .2v.5h1.3M174.3 82.1l.5 1.3 .4-1.3M174.3 84.6l.5 1.3 .4-1.3M174.3 87.2l.5 1.2 .4-1.2"/>
<path d="M174.3 89.7l.5 1.3 .4-1.3M175.2 80.1l-.1-.7h-.4l-.2 .2v.5h1.3M177.7 80.1l-.1-.7h-.4l-.1 .2v.5h1.3M180.3 80.1l-.1-.7h-.4l-.2 .2v.5h1.3M67.7 105v-.3h1.9v.3M70.3 105v-.3h1.8v.3M75.4 105v-.3h1.8v.3M77.9 105v-.3h1.8v.3M83 105v-.3h1.8v.3M85.5 105v-.3h1.9v.3M88.1 105v-.3h1.8v.3M90.6 105v-.3h1.8v.3"/>
<path d="M93.1 106.2v-.3h1.9v.3M95.7 106.2v-.3h1.8v.3M98.2 106.2v-.3h1.9v.3M100.8 106.2v-.3h1.8v.3M103.3 106.2v-.3h1.8v.3M105.8 106.2v-.3h1.9v.3M108.4 106.2v-.3h1.8v.3M110.9 106.2v-.3h1.9v.3M113.5 106.2v-.3h1.8v.3M116 106.2v-.3h1.8v.3M121.1 105v-.3h1.8v.3M123.6 105v-.3h1.9v.3"/>
<path d="M126.2 105v-.3h1.8v.3M128.7 105v-.3h1.8v.3M131.2 105v-.3h1.9v.3M132.6 105.9l-1.2-.6v.9M133.8 105v-.3h1.8v.3M136.3 105v-.3h1.9v.3M138.9 105v-.3h1.8v.3M139.8 105.3v.8l-.9-.3M141.4 105v-.3h1.8v.3M143.9 105v-.3h1.9v.3M146.5 105v-.3h1.8v.3M149 105v-.3h1.9v.3"/>
<path d="M151.6 105v-.3h1.8v.3M154.1 105v-.3h1.8v.3M156.6 105v-.3h1.9v.3M158 105.9l-1.2-.6v.9M159.2 105v-.3h1.8v.3M161.7 105v-.3h1.9v.3M164.3 105v-.3h1.8v.3M165.2 105.3v.8l-.9-.3M166.8 105v-.3h1.8v.3M169.3 106.2v-.3h1.9v.3M171.9 106.2v-.3h1.8v.3M174.4 106.2v-.3h1.9v.3"/>
<path d="M177 106.2v-.3h1.8v.3M179.5 106.2v-.3h1.8v.3M40.8 159.6v-1.3l.4 .9 .5-.9v1.3M42.3 155.8l-.4-.1-.3 .3 .1 .3 .6 .2v.4l-.2 .1h-.5M42.5 148.2l-.5-.1-.1 .2v.4l.6 .2v.3l-.2 .2-.5-.1M42.6 145.7l-.5-.1-.2 .1v.4l.6 .2 .1 .3-.3 .3-.4-.1M40.8 162.1v-1.3l.4 .9 .5-.9v1.3M43.7 163.5a.6 .6 0 0 0-.9 .4 .6 .6 0 0 0 .6 .7l.3-.1M48.9 178.1v.2M48.9 178.6v.8"/>
</g>
<g fill="none" stroke="#008400" stroke-width=".18">
<path d="M19 23.1h71.2M19 28.2h71.2M78.7 39.6v1.3M88.9 39.6v1.3M110.5 29.5h17.8M116.8 25.6v3.9M116.8 34.5v5.1h11.5M210.8 35.8h24.1M218.4 20.6v1.2M222.2 38.3h12.7M222.2 33.3h12.7M222.2 30.7h12.7"/>
<path d="M226.1 21.8v1.3M226.1 28.2v2.5M229.9 38.3v6.4M232.4 23.1v-1.3h-21.6v34.3h24.1v-5.1M232.4 28.2v5.1M74.9 40.9v-1.3h17.8v30.5h1.3M78.7 46v24.1M86.4 54.9h2.5M88.9 46v12.7h-7.6v11.4M222.2 43.4h12.7M223.5 43.4v1.3M223.5 49.8v1.2"/>
<path d="M229.9 49.8v1.2h-19.1M234.9 40.9h-22.8v19h66v-8.9M234.9 48.5h-3.8v5.1M59.7 93h1.3M59.7 95.5h1.3M59.7 85.3h1.3M59.7 87.9h1.3M59.7 90.4h1.3M59.7 98h1.3M61 82.8h-1.3v19M188 82.8h10.1M188 93h1.2"/>
<path d="M188 95.5h1.2M188 85.3h1.2M188 87.9h1.2M188 90.4h1.2M189.2 82.8v15.2h-1.2M198.1 81.5v19.1h-2.5M59.7 100.6h1.3M91.4 115.8v11.4M188 100.6h2.5v2.5h-2.5M240 118.4h16.5M243.8 113.3v5.1M251.5 118.4v7.6"/>
<path d="M256.5 103.1v5.1M256.5 110.7v5.1M91.4 123.4h-3.8v1.3M240 120.9h16.5M242.6 120.9v5.1M251.5 131.1v1.2M256.5 123.4v8.9h-13.9v-1.2M24.1 153.9v21.6h17.8M24.1 143.8v2.5M52.1 156.5h15.2M52.1 159h10.1M52.1 148.8h7.6"/>
<path d="M41.9 174.2v6.4M52.1 161.5h5M102.9 178h7.6M102.9 170.4h7.6M102.9 175.5h15.2M102.9 167.9h15.2M110.5 173h15.2M118.1 178h7.6M118.1 170.4h7.6M125.7 180.6h-1.2v1.3"/>
</g>
<g fill="#008400" stroke="#008400" stroke-width=".25">
<circle cx="78.7" cy="54.9" r=".51"/>
<circle cx="29.2" cy="28.2" r=".51"/>
<circle cx="210.8" cy="51" r=".51"/>
<circle cx="189.2" cy="90.4" r=".51"/>
<circle cx="189.2" cy="93" r=".51"/>
<circle cx="59.7" cy="87.9" r=".51"/>
<circle cx="190.5" cy="100.6" r=".51"/>
<circle cx="189.2" cy="82.8" r=".51"/>
<circle cx="198.1" cy="82.8" r=".51"/>
<circle cx="190.5" cy="103.1" r=".51"/>
<circle cx="88.9" cy="54.9" r=".51"/>
<circle cx="256.5" cy="132.3" r=".51"/>
<circle cx="251.5" cy="132.3" r=".51"/>
<circle cx="229.9" cy="38.3" r=".51"/>
<circle cx="189.2" cy="95.5" r=".51"/>
<circle cx="251.5" cy="118.4" r=".51"/>
<circle cx="78.7" cy="39.6" r=".51"/>
<circle cx="242.6" cy="120.9" r=".51"/>
<circle cx="250.2" cy="59.9" r=".51"/>
<circle cx="243.8" cy="118.4" r=".51"/>
<circle cx="226.1" cy="30.7" r=".51"/>
<circle cx="232.4" cy="33.3" r=".51"/>
<circle cx="226.1" cy="21.8" r=".51"/>
<circle cx="218.4" cy="21.8" r=".51"/>
<circle cx="41.9" cy="175.5" r=".51"/>
<circle cx="210.8" cy="35.8" r=".51"/>
<circle cx="223.5" cy="51" r=".51"/>
<circle cx="69.9" cy="28.2" r=".51"/>
<circle cx="59.7" cy="85.3" r=".51"/>
<circle cx="49.5" cy="28.2" r=".51"/>
<circle cx="49.5" cy="23.1" r=".51"/>
<circle cx="34.3" cy="28.2" r=".51"/>
<circle cx="34.3" cy="23.1" r=".51"/>
<circle cx="69.9" cy="23.1" r=".51"/>
<circle cx="223.5" cy="43.4" r=".51"/>
<circle cx="80" cy="23.1" r=".51"/>
<circle cx="59.7" cy="28.2" r=".51"/>
<circle cx="39.4" cy="28.2" r=".51"/>
<circle cx="80" cy="28.2" r=".51"/>
<circle cx="116.8" cy="29.5" r=".51"/>
<circle cx="59.7" cy="100.6" r=".51"/>
<circle cx="29.2" cy="23.1" r=".51"/>
<circle cx="39.4" cy="23.1" r=".51"/>
<circle cx="189.2" cy="87.9" r=".51"/>
<circle cx="189.2" cy="85.3" r=".51"/>
<circle cx="124.5" cy="39.6" r=".51"/>
<circle cx="59.7" cy="23.1" r=".51"/>
<circle cx="91.4" cy="123.4" r=".51"/>
<circle cx="88.9" cy="39.6" r=".51"/>
<circle cx="59.7" cy="98" r=".51"/>
<circle cx="59.7" cy="95.5" r=".51"/>
<circle cx="59.7" cy="93" r=".51"/>
<circle cx="59.7" cy="90.4" r=".51"/>
</g>
<g fill="none" stroke="#000084" stroke-width=".18">
<path d="M234.3 27.6l1.3 1.2M235.6 27.6l-1.3 1.2M234.3 45.4l1.3 1.2M235.6 45.4l-1.3 1.2M43.8 133l1.3 1.2M45.1 133l-1.3 1.2M31.1 150.8l1.3 1.2M31.1 153.3l1.3 1.2M32.4 150.8l-1.3 1.2M32.4 153.3l-1.3 1.2M51.5 140.6l1.2 1.2M51.5 143.1l1.2 1.3"/>
<path d="M51.5 145.7l1.2 1.2M51.5 153.3l1.2 1.2M52.7 140.6l-1.2 1.2M52.7 143.1l-1.2 1.3M52.7 145.7l-1.2 1.2M52.7 153.3l-1.2 1.2"/>
</g>
<use href="#words"/>
</svg>
